VERSION 5.8 ;
BUSBITCHARS "[]" ;
DIVIDERCHAR "/" ;
UNITS
    DATABASE MICRONS 1000 ;
END UNITS

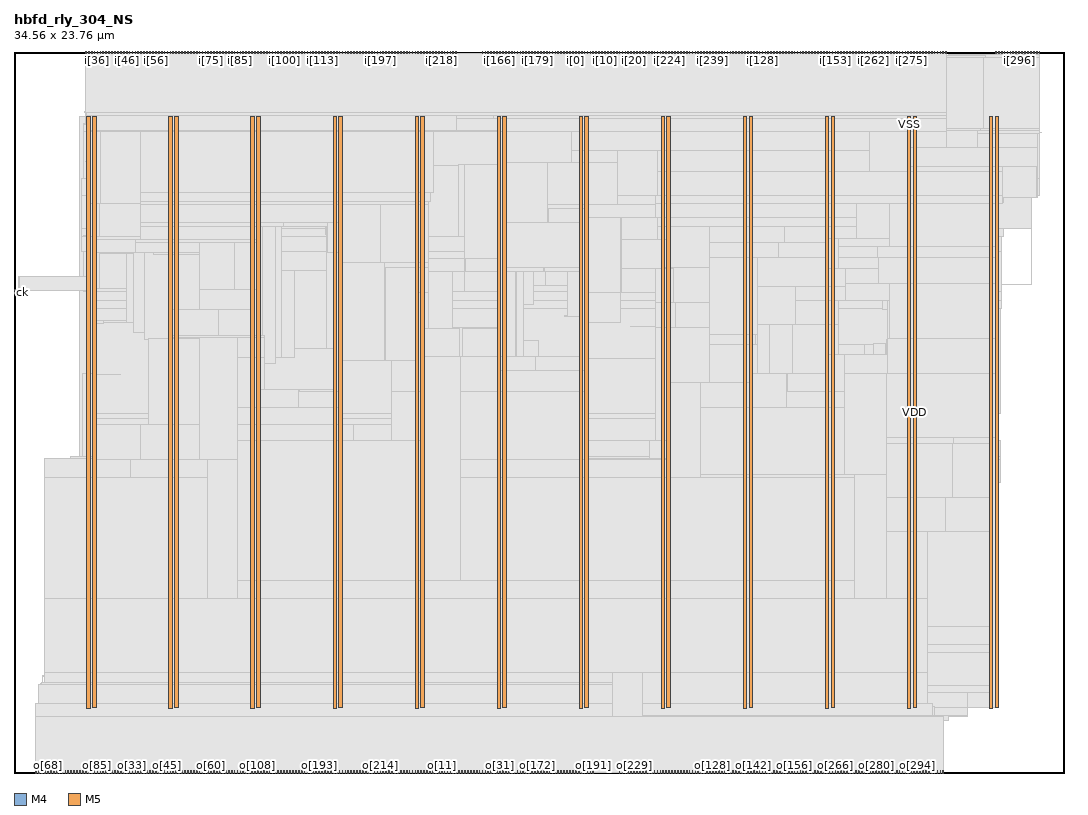
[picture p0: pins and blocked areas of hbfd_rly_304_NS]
MACRO hbfd_rly_304_NS
  FOREIGN hbfd_rly_304_NS 0 0 ;
  CLASS BLOCK ;
  SIZE 34.56 BY 23.76 ;
  PIN ck
    DIRECTION INPUT ;
    USE SIGNAL ;
    PORT
      LAYER M4 ;
        RECT  0 15.792 0.084 15.816 ;
    END
  END ck
  PIN i[0]
    DIRECTION INPUT ;
    USE SIGNAL ;
    PORT
      LAYER M5 ;
        RECT  18.48 23.676 18.504 23.76 ;
    END
  END i[0]
  PIN i[100]
    DIRECTION INPUT ;
    USE SIGNAL ;
    PORT
      LAYER M5 ;
        RECT  8.88 23.676 8.904 23.76 ;
    END
  END i[100]
  PIN i[101]
    DIRECTION INPUT ;
    USE SIGNAL ;
    PORT
      LAYER M5 ;
        RECT  8.976 23.676 9 23.76 ;
    END
  END i[101]
  PIN i[102]
    DIRECTION INPUT ;
    USE SIGNAL ;
    PORT
      LAYER M5 ;
        RECT  9.072 23.676 9.096 23.76 ;
    END
  END i[102]
  PIN i[103]
    DIRECTION INPUT ;
    USE SIGNAL ;
    PORT
      LAYER M5 ;
        RECT  9.168 23.676 9.192 23.76 ;
    END
  END i[103]
  PIN i[104]
    DIRECTION INPUT ;
    USE SIGNAL ;
    PORT
      LAYER M5 ;
        RECT  9.264 23.676 9.288 23.76 ;
    END
  END i[104]
  PIN i[105]
    DIRECTION INPUT ;
    USE SIGNAL ;
    PORT
      LAYER M5 ;
        RECT  9.36 23.676 9.384 23.76 ;
    END
  END i[105]
  PIN i[106]
    DIRECTION INPUT ;
    USE SIGNAL ;
    PORT
      LAYER M5 ;
        RECT  9.456 23.676 9.48 23.76 ;
    END
  END i[106]
  PIN i[107]
    DIRECTION INPUT ;
    USE SIGNAL ;
    PORT
      LAYER M5 ;
        RECT  9.552 23.676 9.576 23.76 ;
    END
  END i[107]
  PIN i[108]
    DIRECTION INPUT ;
    USE SIGNAL ;
    PORT
      LAYER M5 ;
        RECT  9.648 23.676 9.672 23.76 ;
    END
  END i[108]
  PIN i[109]
    DIRECTION INPUT ;
    USE SIGNAL ;
    PORT
      LAYER M5 ;
        RECT  9.744 23.676 9.768 23.76 ;
    END
  END i[109]
  PIN i[10]
    DIRECTION INPUT ;
    USE SIGNAL ;
    PORT
      LAYER M5 ;
        RECT  19.44 23.676 19.464 23.76 ;
    END
  END i[10]
  PIN i[110]
    DIRECTION INPUT ;
    USE SIGNAL ;
    PORT
      LAYER M5 ;
        RECT  9.84 23.676 9.864 23.76 ;
    END
  END i[110]
  PIN i[111]
    DIRECTION INPUT ;
    USE SIGNAL ;
    PORT
      LAYER M5 ;
        RECT  9.936 23.676 9.96 23.76 ;
    END
  END i[111]
  PIN i[112]
    DIRECTION INPUT ;
    USE SIGNAL ;
    PORT
      LAYER M5 ;
        RECT  10.032 23.676 10.056 23.76 ;
    END
  END i[112]
  PIN i[113]
    DIRECTION INPUT ;
    USE SIGNAL ;
    PORT
      LAYER M5 ;
        RECT  10.128 23.676 10.152 23.76 ;
    END
  END i[113]
  PIN i[114]
    DIRECTION INPUT ;
    USE SIGNAL ;
    PORT
      LAYER M5 ;
        RECT  10.224 23.676 10.248 23.76 ;
    END
  END i[114]
  PIN i[115]
    DIRECTION INPUT ;
    USE SIGNAL ;
    PORT
      LAYER M5 ;
        RECT  10.32 23.676 10.344 23.76 ;
    END
  END i[115]
  PIN i[116]
    DIRECTION INPUT ;
    USE SIGNAL ;
    PORT
      LAYER M5 ;
        RECT  10.416 23.676 10.44 23.76 ;
    END
  END i[116]
  PIN i[117]
    DIRECTION INPUT ;
    USE SIGNAL ;
    PORT
      LAYER M5 ;
        RECT  10.512 23.676 10.536 23.76 ;
    END
  END i[117]
  PIN i[118]
    DIRECTION INPUT ;
    USE SIGNAL ;
    PORT
      LAYER M5 ;
        RECT  10.608 23.676 10.632 23.76 ;
    END
  END i[118]
  PIN i[119]
    DIRECTION INPUT ;
    USE SIGNAL ;
    PORT
      LAYER M5 ;
        RECT  10.704 23.676 10.728 23.76 ;
    END
  END i[119]
  PIN i[11]
    DIRECTION INPUT ;
    USE SIGNAL ;
    PORT
      LAYER M5 ;
        RECT  19.536 23.676 19.56 23.76 ;
    END
  END i[11]
  PIN i[120]
    DIRECTION INPUT ;
    USE SIGNAL ;
    PORT
      LAYER M5 ;
        RECT  10.8 23.676 10.824 23.76 ;
    END
  END i[120]
  PIN i[121]
    DIRECTION INPUT ;
    USE SIGNAL ;
    PORT
      LAYER M5 ;
        RECT  10.896 23.676 10.92 23.76 ;
    END
  END i[121]
  PIN i[122]
    DIRECTION INPUT ;
    USE SIGNAL ;
    PORT
      LAYER M5 ;
        RECT  10.992 23.676 11.016 23.76 ;
    END
  END i[122]
  PIN i[123]
    DIRECTION INPUT ;
    USE SIGNAL ;
    PORT
      LAYER M5 ;
        RECT  11.088 23.676 11.112 23.76 ;
    END
  END i[123]
  PIN i[124]
    DIRECTION INPUT ;
    USE SIGNAL ;
    PORT
      LAYER M5 ;
        RECT  11.184 23.676 11.208 23.76 ;
    END
  END i[124]
  PIN i[125]
    DIRECTION INPUT ;
    USE SIGNAL ;
    PORT
      LAYER M5 ;
        RECT  11.28 23.676 11.304 23.76 ;
    END
  END i[125]
  PIN i[126]
    DIRECTION INPUT ;
    USE SIGNAL ;
    PORT
      LAYER M5 ;
        RECT  11.376 23.676 11.4 23.76 ;
    END
  END i[126]
  PIN i[127]
    DIRECTION INPUT ;
    USE SIGNAL ;
    PORT
      LAYER M5 ;
        RECT  11.472 23.676 11.496 23.76 ;
    END
  END i[127]
  PIN i[128]
    DIRECTION INPUT ;
    USE SIGNAL ;
    PORT
      LAYER M5 ;
        RECT  24.624 23.676 24.648 23.76 ;
    END
  END i[128]
  PIN i[129]
    DIRECTION INPUT ;
    USE SIGNAL ;
    PORT
      LAYER M5 ;
        RECT  24.72 23.676 24.744 23.76 ;
    END
  END i[129]
  PIN i[12]
    DIRECTION INPUT ;
    USE SIGNAL ;
    PORT
      LAYER M5 ;
        RECT  19.632 23.676 19.656 23.76 ;
    END
  END i[12]
  PIN i[130]
    DIRECTION INPUT ;
    USE SIGNAL ;
    PORT
      LAYER M5 ;
        RECT  24.816 23.676 24.84 23.76 ;
    END
  END i[130]
  PIN i[131]
    DIRECTION INPUT ;
    USE SIGNAL ;
    PORT
      LAYER M5 ;
        RECT  24.912 23.676 24.936 23.76 ;
    END
  END i[131]
  PIN i[132]
    DIRECTION INPUT ;
    USE SIGNAL ;
    PORT
      LAYER M5 ;
        RECT  25.008 23.676 25.032 23.76 ;
    END
  END i[132]
  PIN i[133]
    DIRECTION INPUT ;
    USE SIGNAL ;
    PORT
      LAYER M5 ;
        RECT  25.104 23.676 25.128 23.76 ;
    END
  END i[133]
  PIN i[134]
    DIRECTION INPUT ;
    USE SIGNAL ;
    PORT
      LAYER M5 ;
        RECT  25.2 23.676 25.224 23.76 ;
    END
  END i[134]
  PIN i[135]
    DIRECTION INPUT ;
    USE SIGNAL ;
    PORT
      LAYER M5 ;
        RECT  25.296 23.676 25.32 23.76 ;
    END
  END i[135]
  PIN i[136]
    DIRECTION INPUT ;
    USE SIGNAL ;
    PORT
      LAYER M5 ;
        RECT  25.392 23.676 25.416 23.76 ;
    END
  END i[136]
  PIN i[137]
    DIRECTION INPUT ;
    USE SIGNAL ;
    PORT
      LAYER M5 ;
        RECT  25.488 23.676 25.512 23.76 ;
    END
  END i[137]
  PIN i[138]
    DIRECTION INPUT ;
    USE SIGNAL ;
    PORT
      LAYER M5 ;
        RECT  25.584 23.676 25.608 23.76 ;
    END
  END i[138]
  PIN i[139]
    DIRECTION INPUT ;
    USE SIGNAL ;
    PORT
      LAYER M5 ;
        RECT  25.68 23.676 25.704 23.76 ;
    END
  END i[139]
  PIN i[13]
    DIRECTION INPUT ;
    USE SIGNAL ;
    PORT
      LAYER M5 ;
        RECT  19.728 23.676 19.752 23.76 ;
    END
  END i[13]
  PIN i[140]
    DIRECTION INPUT ;
    USE SIGNAL ;
    PORT
      LAYER M5 ;
        RECT  25.776 23.676 25.8 23.76 ;
    END
  END i[140]
  PIN i[141]
    DIRECTION INPUT ;
    USE SIGNAL ;
    PORT
      LAYER M5 ;
        RECT  25.872 23.676 25.896 23.76 ;
    END
  END i[141]
  PIN i[142]
    DIRECTION INPUT ;
    USE SIGNAL ;
    PORT
      LAYER M5 ;
        RECT  25.968 23.676 25.992 23.76 ;
    END
  END i[142]
  PIN i[143]
    DIRECTION INPUT ;
    USE SIGNAL ;
    PORT
      LAYER M5 ;
        RECT  26.064 23.676 26.088 23.76 ;
    END
  END i[143]
  PIN i[144]
    DIRECTION INPUT ;
    USE SIGNAL ;
    PORT
      LAYER M5 ;
        RECT  26.16 23.676 26.184 23.76 ;
    END
  END i[144]
  PIN i[145]
    DIRECTION INPUT ;
    USE SIGNAL ;
    PORT
      LAYER M5 ;
        RECT  26.256 23.676 26.28 23.76 ;
    END
  END i[145]
  PIN i[146]
    DIRECTION INPUT ;
    USE SIGNAL ;
    PORT
      LAYER M5 ;
        RECT  26.352 23.676 26.376 23.76 ;
    END
  END i[146]
  PIN i[147]
    DIRECTION INPUT ;
    USE SIGNAL ;
    PORT
      LAYER M5 ;
        RECT  26.448 23.676 26.472 23.76 ;
    END
  END i[147]
  PIN i[148]
    DIRECTION INPUT ;
    USE SIGNAL ;
    PORT
      LAYER M5 ;
        RECT  26.544 23.676 26.568 23.76 ;
    END
  END i[148]
  PIN i[149]
    DIRECTION INPUT ;
    USE SIGNAL ;
    PORT
      LAYER M5 ;
        RECT  26.64 23.676 26.664 23.76 ;
    END
  END i[149]
  PIN i[14]
    DIRECTION INPUT ;
    USE SIGNAL ;
    PORT
      LAYER M5 ;
        RECT  19.824 23.676 19.848 23.76 ;
    END
  END i[14]
  PIN i[150]
    DIRECTION INPUT ;
    USE SIGNAL ;
    PORT
      LAYER M5 ;
        RECT  26.736 23.676 26.76 23.76 ;
    END
  END i[150]
  PIN i[151]
    DIRECTION INPUT ;
    USE SIGNAL ;
    PORT
      LAYER M5 ;
        RECT  26.832 23.676 26.856 23.76 ;
    END
  END i[151]
  PIN i[152]
    DIRECTION INPUT ;
    USE SIGNAL ;
    PORT
      LAYER M5 ;
        RECT  26.928 23.676 26.952 23.76 ;
    END
  END i[152]
  PIN i[153]
    DIRECTION INPUT ;
    USE SIGNAL ;
    PORT
      LAYER M5 ;
        RECT  27.024 23.676 27.048 23.76 ;
    END
  END i[153]
  PIN i[154]
    DIRECTION INPUT ;
    USE SIGNAL ;
    PORT
      LAYER M5 ;
        RECT  27.12 23.676 27.144 23.76 ;
    END
  END i[154]
  PIN i[155]
    DIRECTION INPUT ;
    USE SIGNAL ;
    PORT
      LAYER M5 ;
        RECT  27.216 23.676 27.24 23.76 ;
    END
  END i[155]
  PIN i[156]
    DIRECTION INPUT ;
    USE SIGNAL ;
    PORT
      LAYER M5 ;
        RECT  27.312 23.676 27.336 23.76 ;
    END
  END i[156]
  PIN i[157]
    DIRECTION INPUT ;
    USE SIGNAL ;
    PORT
      LAYER M5 ;
        RECT  27.408 23.676 27.432 23.76 ;
    END
  END i[157]
  PIN i[158]
    DIRECTION INPUT ;
    USE SIGNAL ;
    PORT
      LAYER M5 ;
        RECT  27.504 23.676 27.528 23.76 ;
    END
  END i[158]
  PIN i[159]
    DIRECTION INPUT ;
    USE SIGNAL ;
    PORT
      LAYER M5 ;
        RECT  27.6 23.676 27.624 23.76 ;
    END
  END i[159]
  PIN i[15]
    DIRECTION INPUT ;
    USE SIGNAL ;
    PORT
      LAYER M5 ;
        RECT  19.92 23.676 19.944 23.76 ;
    END
  END i[15]
  PIN i[160]
    DIRECTION INPUT ;
    USE SIGNAL ;
    PORT
      LAYER M5 ;
        RECT  15.408 23.676 15.432 23.76 ;
    END
  END i[160]
  PIN i[161]
    DIRECTION INPUT ;
    USE SIGNAL ;
    PORT
      LAYER M5 ;
        RECT  15.504 23.676 15.528 23.76 ;
    END
  END i[161]
  PIN i[162]
    DIRECTION INPUT ;
    USE SIGNAL ;
    PORT
      LAYER M5 ;
        RECT  15.6 23.676 15.624 23.76 ;
    END
  END i[162]
  PIN i[163]
    DIRECTION INPUT ;
    USE SIGNAL ;
    PORT
      LAYER M5 ;
        RECT  15.696 23.676 15.72 23.76 ;
    END
  END i[163]
  PIN i[164]
    DIRECTION INPUT ;
    USE SIGNAL ;
    PORT
      LAYER M5 ;
        RECT  15.792 23.676 15.816 23.76 ;
    END
  END i[164]
  PIN i[165]
    DIRECTION INPUT ;
    USE SIGNAL ;
    PORT
      LAYER M5 ;
        RECT  15.888 23.676 15.912 23.76 ;
    END
  END i[165]
  PIN i[166]
    DIRECTION INPUT ;
    USE SIGNAL ;
    PORT
      LAYER M5 ;
        RECT  15.984 23.676 16.008 23.76 ;
    END
  END i[166]
  PIN i[167]
    DIRECTION INPUT ;
    USE SIGNAL ;
    PORT
      LAYER M5 ;
        RECT  16.08 23.676 16.104 23.76 ;
    END
  END i[167]
  PIN i[168]
    DIRECTION INPUT ;
    USE SIGNAL ;
    PORT
      LAYER M5 ;
        RECT  16.176 23.676 16.2 23.76 ;
    END
  END i[168]
  PIN i[169]
    DIRECTION INPUT ;
    USE SIGNAL ;
    PORT
      LAYER M5 ;
        RECT  16.272 23.676 16.296 23.76 ;
    END
  END i[169]
  PIN i[16]
    DIRECTION INPUT ;
    USE SIGNAL ;
    PORT
      LAYER M5 ;
        RECT  20.016 23.676 20.04 23.76 ;
    END
  END i[16]
  PIN i[170]
    DIRECTION INPUT ;
    USE SIGNAL ;
    PORT
      LAYER M5 ;
        RECT  16.368 23.676 16.392 23.76 ;
    END
  END i[170]
  PIN i[171]
    DIRECTION INPUT ;
    USE SIGNAL ;
    PORT
      LAYER M5 ;
        RECT  16.464 23.676 16.488 23.76 ;
    END
  END i[171]
  PIN i[172]
    DIRECTION INPUT ;
    USE SIGNAL ;
    PORT
      LAYER M5 ;
        RECT  16.56 23.676 16.584 23.76 ;
    END
  END i[172]
  PIN i[173]
    DIRECTION INPUT ;
    USE SIGNAL ;
    PORT
      LAYER M5 ;
        RECT  16.656 23.676 16.68 23.76 ;
    END
  END i[173]
  PIN i[174]
    DIRECTION INPUT ;
    USE SIGNAL ;
    PORT
      LAYER M5 ;
        RECT  16.752 23.676 16.776 23.76 ;
    END
  END i[174]
  PIN i[175]
    DIRECTION INPUT ;
    USE SIGNAL ;
    PORT
      LAYER M5 ;
        RECT  16.848 23.676 16.872 23.76 ;
    END
  END i[175]
  PIN i[176]
    DIRECTION INPUT ;
    USE SIGNAL ;
    PORT
      LAYER M5 ;
        RECT  16.944 23.676 16.968 23.76 ;
    END
  END i[176]
  PIN i[177]
    DIRECTION INPUT ;
    USE SIGNAL ;
    PORT
      LAYER M5 ;
        RECT  17.04 23.676 17.064 23.76 ;
    END
  END i[177]
  PIN i[178]
    DIRECTION INPUT ;
    USE SIGNAL ;
    PORT
      LAYER M5 ;
        RECT  17.136 23.676 17.16 23.76 ;
    END
  END i[178]
  PIN i[179]
    DIRECTION INPUT ;
    USE SIGNAL ;
    PORT
      LAYER M5 ;
        RECT  17.232 23.676 17.256 23.76 ;
    END
  END i[179]
  PIN i[17]
    DIRECTION INPUT ;
    USE SIGNAL ;
    PORT
      LAYER M5 ;
        RECT  20.112 23.676 20.136 23.76 ;
    END
  END i[17]
  PIN i[180]
    DIRECTION INPUT ;
    USE SIGNAL ;
    PORT
      LAYER M5 ;
        RECT  17.328 23.676 17.352 23.76 ;
    END
  END i[180]
  PIN i[181]
    DIRECTION INPUT ;
    USE SIGNAL ;
    PORT
      LAYER M5 ;
        RECT  17.424 23.676 17.448 23.76 ;
    END
  END i[181]
  PIN i[182]
    DIRECTION INPUT ;
    USE SIGNAL ;
    PORT
      LAYER M5 ;
        RECT  17.52 23.676 17.544 23.76 ;
    END
  END i[182]
  PIN i[183]
    DIRECTION INPUT ;
    USE SIGNAL ;
    PORT
      LAYER M5 ;
        RECT  17.616 23.676 17.64 23.76 ;
    END
  END i[183]
  PIN i[184]
    DIRECTION INPUT ;
    USE SIGNAL ;
    PORT
      LAYER M5 ;
        RECT  17.712 23.676 17.736 23.76 ;
    END
  END i[184]
  PIN i[185]
    DIRECTION INPUT ;
    USE SIGNAL ;
    PORT
      LAYER M5 ;
        RECT  17.808 23.676 17.832 23.76 ;
    END
  END i[185]
  PIN i[186]
    DIRECTION INPUT ;
    USE SIGNAL ;
    PORT
      LAYER M5 ;
        RECT  17.904 23.676 17.928 23.76 ;
    END
  END i[186]
  PIN i[187]
    DIRECTION INPUT ;
    USE SIGNAL ;
    PORT
      LAYER M5 ;
        RECT  18 23.676 18.024 23.76 ;
    END
  END i[187]
  PIN i[188]
    DIRECTION INPUT ;
    USE SIGNAL ;
    PORT
      LAYER M5 ;
        RECT  18.096 23.676 18.12 23.76 ;
    END
  END i[188]
  PIN i[189]
    DIRECTION INPUT ;
    USE SIGNAL ;
    PORT
      LAYER M5 ;
        RECT  18.192 23.676 18.216 23.76 ;
    END
  END i[189]
  PIN i[18]
    DIRECTION INPUT ;
    USE SIGNAL ;
    PORT
      LAYER M5 ;
        RECT  20.208 23.676 20.232 23.76 ;
    END
  END i[18]
  PIN i[190]
    DIRECTION INPUT ;
    USE SIGNAL ;
    PORT
      LAYER M5 ;
        RECT  18.288 23.676 18.312 23.76 ;
    END
  END i[190]
  PIN i[191]
    DIRECTION INPUT ;
    USE SIGNAL ;
    PORT
      LAYER M5 ;
        RECT  18.384 23.676 18.408 23.76 ;
    END
  END i[191]
  PIN i[192]
    DIRECTION INPUT ;
    USE SIGNAL ;
    PORT
      LAYER M5 ;
        RECT  11.568 23.676 11.592 23.76 ;
    END
  END i[192]
  PIN i[193]
    DIRECTION INPUT ;
    USE SIGNAL ;
    PORT
      LAYER M5 ;
        RECT  11.664 23.676 11.688 23.76 ;
    END
  END i[193]
  PIN i[194]
    DIRECTION INPUT ;
    USE SIGNAL ;
    PORT
      LAYER M5 ;
        RECT  11.76 23.676 11.784 23.76 ;
    END
  END i[194]
  PIN i[195]
    DIRECTION INPUT ;
    USE SIGNAL ;
    PORT
      LAYER M5 ;
        RECT  11.856 23.676 11.88 23.76 ;
    END
  END i[195]
  PIN i[196]
    DIRECTION INPUT ;
    USE SIGNAL ;
    PORT
      LAYER M5 ;
        RECT  11.952 23.676 11.976 23.76 ;
    END
  END i[196]
  PIN i[197]
    DIRECTION INPUT ;
    USE SIGNAL ;
    PORT
      LAYER M5 ;
        RECT  12.048 23.676 12.072 23.76 ;
    END
  END i[197]
  PIN i[198]
    DIRECTION INPUT ;
    USE SIGNAL ;
    PORT
      LAYER M5 ;
        RECT  12.144 23.676 12.168 23.76 ;
    END
  END i[198]
  PIN i[199]
    DIRECTION INPUT ;
    USE SIGNAL ;
    PORT
      LAYER M5 ;
        RECT  12.24 23.676 12.264 23.76 ;
    END
  END i[199]
  PIN i[19]
    DIRECTION INPUT ;
    USE SIGNAL ;
    PORT
      LAYER M5 ;
        RECT  20.304 23.676 20.328 23.76 ;
    END
  END i[19]
  PIN i[1]
    DIRECTION INPUT ;
    USE SIGNAL ;
    PORT
      LAYER M5 ;
        RECT  18.576 23.676 18.6 23.76 ;
    END
  END i[1]
  PIN i[200]
    DIRECTION INPUT ;
    USE SIGNAL ;
    PORT
      LAYER M5 ;
        RECT  12.336 23.676 12.36 23.76 ;
    END
  END i[200]
  PIN i[201]
    DIRECTION INPUT ;
    USE SIGNAL ;
    PORT
      LAYER M5 ;
        RECT  12.432 23.676 12.456 23.76 ;
    END
  END i[201]
  PIN i[202]
    DIRECTION INPUT ;
    USE SIGNAL ;
    PORT
      LAYER M5 ;
        RECT  12.528 23.676 12.552 23.76 ;
    END
  END i[202]
  PIN i[203]
    DIRECTION INPUT ;
    USE SIGNAL ;
    PORT
      LAYER M5 ;
        RECT  12.624 23.676 12.648 23.76 ;
    END
  END i[203]
  PIN i[204]
    DIRECTION INPUT ;
    USE SIGNAL ;
    PORT
      LAYER M5 ;
        RECT  12.72 23.676 12.744 23.76 ;
    END
  END i[204]
  PIN i[205]
    DIRECTION INPUT ;
    USE SIGNAL ;
    PORT
      LAYER M5 ;
        RECT  12.816 23.676 12.84 23.76 ;
    END
  END i[205]
  PIN i[206]
    DIRECTION INPUT ;
    USE SIGNAL ;
    PORT
      LAYER M5 ;
        RECT  12.912 23.676 12.936 23.76 ;
    END
  END i[206]
  PIN i[207]
    DIRECTION INPUT ;
    USE SIGNAL ;
    PORT
      LAYER M5 ;
        RECT  13.008 23.676 13.032 23.76 ;
    END
  END i[207]
  PIN i[208]
    DIRECTION INPUT ;
    USE SIGNAL ;
    PORT
      LAYER M5 ;
        RECT  13.104 23.676 13.128 23.76 ;
    END
  END i[208]
  PIN i[209]
    DIRECTION INPUT ;
    USE SIGNAL ;
    PORT
      LAYER M5 ;
        RECT  13.2 23.676 13.224 23.76 ;
    END
  END i[209]
  PIN i[20]
    DIRECTION INPUT ;
    USE SIGNAL ;
    PORT
      LAYER M5 ;
        RECT  20.4 23.676 20.424 23.76 ;
    END
  END i[20]
  PIN i[210]
    DIRECTION INPUT ;
    USE SIGNAL ;
    PORT
      LAYER M5 ;
        RECT  13.296 23.676 13.32 23.76 ;
    END
  END i[210]
  PIN i[211]
    DIRECTION INPUT ;
    USE SIGNAL ;
    PORT
      LAYER M5 ;
        RECT  13.392 23.676 13.416 23.76 ;
    END
  END i[211]
  PIN i[212]
    DIRECTION INPUT ;
    USE SIGNAL ;
    PORT
      LAYER M5 ;
        RECT  13.488 23.676 13.512 23.76 ;
    END
  END i[212]
  PIN i[213]
    DIRECTION INPUT ;
    USE SIGNAL ;
    PORT
      LAYER M5 ;
        RECT  13.584 23.676 13.608 23.76 ;
    END
  END i[213]
  PIN i[214]
    DIRECTION INPUT ;
    USE SIGNAL ;
    PORT
      LAYER M5 ;
        RECT  13.68 23.676 13.704 23.76 ;
    END
  END i[214]
  PIN i[215]
    DIRECTION INPUT ;
    USE SIGNAL ;
    PORT
      LAYER M5 ;
        RECT  13.776 23.676 13.8 23.76 ;
    END
  END i[215]
  PIN i[216]
    DIRECTION INPUT ;
    USE SIGNAL ;
    PORT
      LAYER M5 ;
        RECT  13.872 23.676 13.896 23.76 ;
    END
  END i[216]
  PIN i[217]
    DIRECTION INPUT ;
    USE SIGNAL ;
    PORT
      LAYER M5 ;
        RECT  13.968 23.676 13.992 23.76 ;
    END
  END i[217]
  PIN i[218]
    DIRECTION INPUT ;
    USE SIGNAL ;
    PORT
      LAYER M5 ;
        RECT  14.064 23.676 14.088 23.76 ;
    END
  END i[218]
  PIN i[219]
    DIRECTION INPUT ;
    USE SIGNAL ;
    PORT
      LAYER M5 ;
        RECT  14.16 23.676 14.184 23.76 ;
    END
  END i[219]
  PIN i[21]
    DIRECTION INPUT ;
    USE SIGNAL ;
    PORT
      LAYER M5 ;
        RECT  20.496 23.676 20.52 23.76 ;
    END
  END i[21]
  PIN i[220]
    DIRECTION INPUT ;
    USE SIGNAL ;
    PORT
      LAYER M5 ;
        RECT  14.256 23.676 14.28 23.76 ;
    END
  END i[220]
  PIN i[221]
    DIRECTION INPUT ;
    USE SIGNAL ;
    PORT
      LAYER M5 ;
        RECT  14.352 23.676 14.376 23.76 ;
    END
  END i[221]
  PIN i[222]
    DIRECTION INPUT ;
    USE SIGNAL ;
    PORT
      LAYER M5 ;
        RECT  14.448 23.676 14.472 23.76 ;
    END
  END i[222]
  PIN i[223]
    DIRECTION INPUT ;
    USE SIGNAL ;
    PORT
      LAYER M5 ;
        RECT  14.544 23.676 14.568 23.76 ;
    END
  END i[223]
  PIN i[224]
    DIRECTION INPUT ;
    USE SIGNAL ;
    PORT
      LAYER M5 ;
        RECT  21.552 23.676 21.576 23.76 ;
    END
  END i[224]
  PIN i[225]
    DIRECTION INPUT ;
    USE SIGNAL ;
    PORT
      LAYER M5 ;
        RECT  21.648 23.676 21.672 23.76 ;
    END
  END i[225]
  PIN i[226]
    DIRECTION INPUT ;
    USE SIGNAL ;
    PORT
      LAYER M5 ;
        RECT  21.744 23.676 21.768 23.76 ;
    END
  END i[226]
  PIN i[227]
    DIRECTION INPUT ;
    USE SIGNAL ;
    PORT
      LAYER M5 ;
        RECT  21.84 23.676 21.864 23.76 ;
    END
  END i[227]
  PIN i[228]
    DIRECTION INPUT ;
    USE SIGNAL ;
    PORT
      LAYER M5 ;
        RECT  21.936 23.676 21.96 23.76 ;
    END
  END i[228]
  PIN i[229]
    DIRECTION INPUT ;
    USE SIGNAL ;
    PORT
      LAYER M5 ;
        RECT  22.032 23.676 22.056 23.76 ;
    END
  END i[229]
  PIN i[22]
    DIRECTION INPUT ;
    USE SIGNAL ;
    PORT
      LAYER M5 ;
        RECT  20.592 23.676 20.616 23.76 ;
    END
  END i[22]
  PIN i[230]
    DIRECTION INPUT ;
    USE SIGNAL ;
    PORT
      LAYER M5 ;
        RECT  22.128 23.676 22.152 23.76 ;
    END
  END i[230]
  PIN i[231]
    DIRECTION INPUT ;
    USE SIGNAL ;
    PORT
      LAYER M5 ;
        RECT  22.224 23.676 22.248 23.76 ;
    END
  END i[231]
  PIN i[232]
    DIRECTION INPUT ;
    USE SIGNAL ;
    PORT
      LAYER M5 ;
        RECT  22.32 23.676 22.344 23.76 ;
    END
  END i[232]
  PIN i[233]
    DIRECTION INPUT ;
    USE SIGNAL ;
    PORT
      LAYER M5 ;
        RECT  22.416 23.676 22.44 23.76 ;
    END
  END i[233]
  PIN i[234]
    DIRECTION INPUT ;
    USE SIGNAL ;
    PORT
      LAYER M5 ;
        RECT  22.512 23.676 22.536 23.76 ;
    END
  END i[234]
  PIN i[235]
    DIRECTION INPUT ;
    USE SIGNAL ;
    PORT
      LAYER M5 ;
        RECT  22.608 23.676 22.632 23.76 ;
    END
  END i[235]
  PIN i[236]
    DIRECTION INPUT ;
    USE SIGNAL ;
    PORT
      LAYER M5 ;
        RECT  22.704 23.676 22.728 23.76 ;
    END
  END i[236]
  PIN i[237]
    DIRECTION INPUT ;
    USE SIGNAL ;
    PORT
      LAYER M5 ;
        RECT  22.8 23.676 22.824 23.76 ;
    END
  END i[237]
  PIN i[238]
    DIRECTION INPUT ;
    USE SIGNAL ;
    PORT
      LAYER M5 ;
        RECT  22.896 23.676 22.92 23.76 ;
    END
  END i[238]
  PIN i[239]
    DIRECTION INPUT ;
    USE SIGNAL ;
    PORT
      LAYER M5 ;
        RECT  22.992 23.676 23.016 23.76 ;
    END
  END i[239]
  PIN i[23]
    DIRECTION INPUT ;
    USE SIGNAL ;
    PORT
      LAYER M5 ;
        RECT  20.688 23.676 20.712 23.76 ;
    END
  END i[23]
  PIN i[240]
    DIRECTION INPUT ;
    USE SIGNAL ;
    PORT
      LAYER M5 ;
        RECT  23.088 23.676 23.112 23.76 ;
    END
  END i[240]
  PIN i[241]
    DIRECTION INPUT ;
    USE SIGNAL ;
    PORT
      LAYER M5 ;
        RECT  23.184 23.676 23.208 23.76 ;
    END
  END i[241]
  PIN i[242]
    DIRECTION INPUT ;
    USE SIGNAL ;
    PORT
      LAYER M5 ;
        RECT  23.28 23.676 23.304 23.76 ;
    END
  END i[242]
  PIN i[243]
    DIRECTION INPUT ;
    USE SIGNAL ;
    PORT
      LAYER M5 ;
        RECT  23.376 23.676 23.4 23.76 ;
    END
  END i[243]
  PIN i[244]
    DIRECTION INPUT ;
    USE SIGNAL ;
    PORT
      LAYER M5 ;
        RECT  23.472 23.676 23.496 23.76 ;
    END
  END i[244]
  PIN i[245]
    DIRECTION INPUT ;
    USE SIGNAL ;
    PORT
      LAYER M5 ;
        RECT  23.568 23.676 23.592 23.76 ;
    END
  END i[245]
  PIN i[246]
    DIRECTION INPUT ;
    USE SIGNAL ;
    PORT
      LAYER M5 ;
        RECT  23.664 23.676 23.688 23.76 ;
    END
  END i[246]
  PIN i[247]
    DIRECTION INPUT ;
    USE SIGNAL ;
    PORT
      LAYER M5 ;
        RECT  23.76 23.676 23.784 23.76 ;
    END
  END i[247]
  PIN i[248]
    DIRECTION INPUT ;
    USE SIGNAL ;
    PORT
      LAYER M5 ;
        RECT  23.856 23.676 23.88 23.76 ;
    END
  END i[248]
  PIN i[249]
    DIRECTION INPUT ;
    USE SIGNAL ;
    PORT
      LAYER M5 ;
        RECT  23.952 23.676 23.976 23.76 ;
    END
  END i[249]
  PIN i[24]
    DIRECTION INPUT ;
    USE SIGNAL ;
    PORT
      LAYER M5 ;
        RECT  20.784 23.676 20.808 23.76 ;
    END
  END i[24]
  PIN i[250]
    DIRECTION INPUT ;
    USE SIGNAL ;
    PORT
      LAYER M5 ;
        RECT  24.048 23.676 24.072 23.76 ;
    END
  END i[250]
  PIN i[251]
    DIRECTION INPUT ;
    USE SIGNAL ;
    PORT
      LAYER M5 ;
        RECT  24.144 23.676 24.168 23.76 ;
    END
  END i[251]
  PIN i[252]
    DIRECTION INPUT ;
    USE SIGNAL ;
    PORT
      LAYER M5 ;
        RECT  24.24 23.676 24.264 23.76 ;
    END
  END i[252]
  PIN i[253]
    DIRECTION INPUT ;
    USE SIGNAL ;
    PORT
      LAYER M5 ;
        RECT  24.336 23.676 24.36 23.76 ;
    END
  END i[253]
  PIN i[254]
    DIRECTION INPUT ;
    USE SIGNAL ;
    PORT
      LAYER M5 ;
        RECT  24.432 23.676 24.456 23.76 ;
    END
  END i[254]
  PIN i[255]
    DIRECTION INPUT ;
    USE SIGNAL ;
    PORT
      LAYER M5 ;
        RECT  24.528 23.676 24.552 23.76 ;
    END
  END i[255]
  PIN i[256]
    DIRECTION INPUT ;
    USE SIGNAL ;
    PORT
      LAYER M5 ;
        RECT  27.696 23.676 27.72 23.76 ;
    END
  END i[256]
  PIN i[257]
    DIRECTION INPUT ;
    USE SIGNAL ;
    PORT
      LAYER M5 ;
        RECT  27.792 23.676 27.816 23.76 ;
    END
  END i[257]
  PIN i[258]
    DIRECTION INPUT ;
    USE SIGNAL ;
    PORT
      LAYER M5 ;
        RECT  27.888 23.676 27.912 23.76 ;
    END
  END i[258]
  PIN i[259]
    DIRECTION INPUT ;
    USE SIGNAL ;
    PORT
      LAYER M5 ;
        RECT  27.984 23.676 28.008 23.76 ;
    END
  END i[259]
  PIN i[25]
    DIRECTION INPUT ;
    USE SIGNAL ;
    PORT
      LAYER M5 ;
        RECT  20.88 23.676 20.904 23.76 ;
    END
  END i[25]
  PIN i[260]
    DIRECTION INPUT ;
    USE SIGNAL ;
    PORT
      LAYER M5 ;
        RECT  28.08 23.676 28.104 23.76 ;
    END
  END i[260]
  PIN i[261]
    DIRECTION INPUT ;
    USE SIGNAL ;
    PORT
      LAYER M5 ;
        RECT  28.176 23.676 28.2 23.76 ;
    END
  END i[261]
  PIN i[262]
    DIRECTION INPUT ;
    USE SIGNAL ;
    PORT
      LAYER M5 ;
        RECT  28.272 23.676 28.296 23.76 ;
    END
  END i[262]
  PIN i[263]
    DIRECTION INPUT ;
    USE SIGNAL ;
    PORT
      LAYER M5 ;
        RECT  28.368 23.676 28.392 23.76 ;
    END
  END i[263]
  PIN i[264]
    DIRECTION INPUT ;
    USE SIGNAL ;
    PORT
      LAYER M5 ;
        RECT  28.464 23.676 28.488 23.76 ;
    END
  END i[264]
  PIN i[265]
    DIRECTION INPUT ;
    USE SIGNAL ;
    PORT
      LAYER M5 ;
        RECT  28.56 23.676 28.584 23.76 ;
    END
  END i[265]
  PIN i[266]
    DIRECTION INPUT ;
    USE SIGNAL ;
    PORT
      LAYER M5 ;
        RECT  28.656 23.676 28.68 23.76 ;
    END
  END i[266]
  PIN i[267]
    DIRECTION INPUT ;
    USE SIGNAL ;
    PORT
      LAYER M5 ;
        RECT  28.752 23.676 28.776 23.76 ;
    END
  END i[267]
  PIN i[268]
    DIRECTION INPUT ;
    USE SIGNAL ;
    PORT
      LAYER M5 ;
        RECT  28.848 23.676 28.872 23.76 ;
    END
  END i[268]
  PIN i[269]
    DIRECTION INPUT ;
    USE SIGNAL ;
    PORT
      LAYER M5 ;
        RECT  28.944 23.676 28.968 23.76 ;
    END
  END i[269]
  PIN i[26]
    DIRECTION INPUT ;
    USE SIGNAL ;
    PORT
      LAYER M5 ;
        RECT  20.976 23.676 21 23.76 ;
    END
  END i[26]
  PIN i[270]
    DIRECTION INPUT ;
    USE SIGNAL ;
    PORT
      LAYER M5 ;
        RECT  29.04 23.676 29.064 23.76 ;
    END
  END i[270]
  PIN i[271]
    DIRECTION INPUT ;
    USE SIGNAL ;
    PORT
      LAYER M5 ;
        RECT  29.136 23.676 29.16 23.76 ;
    END
  END i[271]
  PIN i[272]
    DIRECTION INPUT ;
    USE SIGNAL ;
    PORT
      LAYER M5 ;
        RECT  29.232 23.676 29.256 23.76 ;
    END
  END i[272]
  PIN i[273]
    DIRECTION INPUT ;
    USE SIGNAL ;
    PORT
      LAYER M5 ;
        RECT  29.328 23.676 29.352 23.76 ;
    END
  END i[273]
  PIN i[274]
    DIRECTION INPUT ;
    USE SIGNAL ;
    PORT
      LAYER M5 ;
        RECT  29.424 23.676 29.448 23.76 ;
    END
  END i[274]
  PIN i[275]
    DIRECTION INPUT ;
    USE SIGNAL ;
    PORT
      LAYER M5 ;
        RECT  29.52 23.676 29.544 23.76 ;
    END
  END i[275]
  PIN i[276]
    DIRECTION INPUT ;
    USE SIGNAL ;
    PORT
      LAYER M5 ;
        RECT  29.616 23.676 29.64 23.76 ;
    END
  END i[276]
  PIN i[277]
    DIRECTION INPUT ;
    USE SIGNAL ;
    PORT
      LAYER M5 ;
        RECT  29.712 23.676 29.736 23.76 ;
    END
  END i[277]
  PIN i[278]
    DIRECTION INPUT ;
    USE SIGNAL ;
    PORT
      LAYER M5 ;
        RECT  29.808 23.676 29.832 23.76 ;
    END
  END i[278]
  PIN i[279]
    DIRECTION INPUT ;
    USE SIGNAL ;
    PORT
      LAYER M5 ;
        RECT  29.904 23.676 29.928 23.76 ;
    END
  END i[279]
  PIN i[27]
    DIRECTION INPUT ;
    USE SIGNAL ;
    PORT
      LAYER M5 ;
        RECT  21.072 23.676 21.096 23.76 ;
    END
  END i[27]
  PIN i[280]
    DIRECTION INPUT ;
    USE SIGNAL ;
    PORT
      LAYER M5 ;
        RECT  30 23.676 30.024 23.76 ;
    END
  END i[280]
  PIN i[281]
    DIRECTION INPUT ;
    USE SIGNAL ;
    PORT
      LAYER M5 ;
        RECT  30.096 23.676 30.12 23.76 ;
    END
  END i[281]
  PIN i[282]
    DIRECTION INPUT ;
    USE SIGNAL ;
    PORT
      LAYER M5 ;
        RECT  30.192 23.676 30.216 23.76 ;
    END
  END i[282]
  PIN i[283]
    DIRECTION INPUT ;
    USE SIGNAL ;
    PORT
      LAYER M5 ;
        RECT  30.288 23.676 30.312 23.76 ;
    END
  END i[283]
  PIN i[284]
    DIRECTION INPUT ;
    USE SIGNAL ;
    PORT
      LAYER M5 ;
        RECT  30.384 23.676 30.408 23.76 ;
    END
  END i[284]
  PIN i[285]
    DIRECTION INPUT ;
    USE SIGNAL ;
    PORT
      LAYER M5 ;
        RECT  30.48 23.676 30.504 23.76 ;
    END
  END i[285]
  PIN i[286]
    DIRECTION INPUT ;
    USE SIGNAL ;
    PORT
      LAYER M5 ;
        RECT  30.576 23.676 30.6 23.76 ;
    END
  END i[286]
  PIN i[287]
    DIRECTION INPUT ;
    USE SIGNAL ;
    PORT
      LAYER M5 ;
        RECT  30.672 23.676 30.696 23.76 ;
    END
  END i[287]
  PIN i[288]
    DIRECTION INPUT ;
    USE SIGNAL ;
    PORT
      LAYER M5 ;
        RECT  32.304 23.676 32.328 23.76 ;
    END
  END i[288]
  PIN i[289]
    DIRECTION INPUT ;
    USE SIGNAL ;
    PORT
      LAYER M5 ;
        RECT  32.4 23.676 32.424 23.76 ;
    END
  END i[289]
  PIN i[28]
    DIRECTION INPUT ;
    USE SIGNAL ;
    PORT
      LAYER M5 ;
        RECT  21.168 23.676 21.192 23.76 ;
    END
  END i[28]
  PIN i[290]
    DIRECTION INPUT ;
    USE SIGNAL ;
    PORT
      LAYER M5 ;
        RECT  32.496 23.676 32.52 23.76 ;
    END
  END i[290]
  PIN i[291]
    DIRECTION INPUT ;
    USE SIGNAL ;
    PORT
      LAYER M5 ;
        RECT  32.592 23.676 32.616 23.76 ;
    END
  END i[291]
  PIN i[292]
    DIRECTION INPUT ;
    USE SIGNAL ;
    PORT
      LAYER M5 ;
        RECT  32.688 23.676 32.712 23.76 ;
    END
  END i[292]
  PIN i[293]
    DIRECTION INPUT ;
    USE SIGNAL ;
    PORT
      LAYER M5 ;
        RECT  32.784 23.676 32.808 23.76 ;
    END
  END i[293]
  PIN i[294]
    DIRECTION INPUT ;
    USE SIGNAL ;
    PORT
      LAYER M5 ;
        RECT  32.88 23.676 32.904 23.76 ;
    END
  END i[294]
  PIN i[295]
    DIRECTION INPUT ;
    USE SIGNAL ;
    PORT
      LAYER M5 ;
        RECT  32.976 23.676 33 23.76 ;
    END
  END i[295]
  PIN i[296]
    DIRECTION INPUT ;
    USE SIGNAL ;
    PORT
      LAYER M5 ;
        RECT  33.072 23.676 33.096 23.76 ;
    END
  END i[296]
  PIN i[297]
    DIRECTION INPUT ;
    USE SIGNAL ;
    PORT
      LAYER M5 ;
        RECT  33.168 23.676 33.192 23.76 ;
    END
  END i[297]
  PIN i[298]
    DIRECTION INPUT ;
    USE SIGNAL ;
    PORT
      LAYER M5 ;
        RECT  33.264 23.676 33.288 23.76 ;
    END
  END i[298]
  PIN i[299]
    DIRECTION INPUT ;
    USE SIGNAL ;
    PORT
      LAYER M5 ;
        RECT  33.36 23.676 33.384 23.76 ;
    END
  END i[299]
  PIN i[29]
    DIRECTION INPUT ;
    USE SIGNAL ;
    PORT
      LAYER M5 ;
        RECT  21.264 23.676 21.288 23.76 ;
    END
  END i[29]
  PIN i[2]
    DIRECTION INPUT ;
    USE SIGNAL ;
    PORT
      LAYER M5 ;
        RECT  18.672 23.676 18.696 23.76 ;
    END
  END i[2]
  PIN i[300]
    DIRECTION INPUT ;
    USE SIGNAL ;
    PORT
      LAYER M5 ;
        RECT  33.456 23.676 33.48 23.76 ;
    END
  END i[300]
  PIN i[301]
    DIRECTION INPUT ;
    USE SIGNAL ;
    PORT
      LAYER M5 ;
        RECT  33.552 23.676 33.576 23.76 ;
    END
  END i[301]
  PIN i[302]
    DIRECTION INPUT ;
    USE SIGNAL ;
    PORT
      LAYER M5 ;
        RECT  33.648 23.676 33.672 23.76 ;
    END
  END i[302]
  PIN i[303]
    DIRECTION INPUT ;
    USE SIGNAL ;
    PORT
      LAYER M5 ;
        RECT  33.744 23.676 33.768 23.76 ;
    END
  END i[303]
  PIN i[30]
    DIRECTION INPUT ;
    USE SIGNAL ;
    PORT
      LAYER M5 ;
        RECT  21.36 23.676 21.384 23.76 ;
    END
  END i[30]
  PIN i[31]
    DIRECTION INPUT ;
    USE SIGNAL ;
    PORT
      LAYER M5 ;
        RECT  21.456 23.676 21.48 23.76 ;
    END
  END i[31]
  PIN i[32]
    DIRECTION INPUT ;
    USE SIGNAL ;
    PORT
      LAYER M5 ;
        RECT  2.352 23.676 2.376 23.76 ;
    END
  END i[32]
  PIN i[33]
    DIRECTION INPUT ;
    USE SIGNAL ;
    PORT
      LAYER M5 ;
        RECT  2.448 23.676 2.472 23.76 ;
    END
  END i[33]
  PIN i[34]
    DIRECTION INPUT ;
    USE SIGNAL ;
    PORT
      LAYER M5 ;
        RECT  2.544 23.676 2.568 23.76 ;
    END
  END i[34]
  PIN i[35]
    DIRECTION INPUT ;
    USE SIGNAL ;
    PORT
      LAYER M5 ;
        RECT  2.64 23.676 2.664 23.76 ;
    END
  END i[35]
  PIN i[36]
    DIRECTION INPUT ;
    USE SIGNAL ;
    PORT
      LAYER M5 ;
        RECT  2.736 23.676 2.76 23.76 ;
    END
  END i[36]
  PIN i[37]
    DIRECTION INPUT ;
    USE SIGNAL ;
    PORT
      LAYER M5 ;
        RECT  2.832 23.676 2.856 23.76 ;
    END
  END i[37]
  PIN i[38]
    DIRECTION INPUT ;
    USE SIGNAL ;
    PORT
      LAYER M5 ;
        RECT  2.928 23.676 2.952 23.76 ;
    END
  END i[38]
  PIN i[39]
    DIRECTION INPUT ;
    USE SIGNAL ;
    PORT
      LAYER M5 ;
        RECT  3.024 23.676 3.048 23.76 ;
    END
  END i[39]
  PIN i[3]
    DIRECTION INPUT ;
    USE SIGNAL ;
    PORT
      LAYER M5 ;
        RECT  18.768 23.676 18.792 23.76 ;
    END
  END i[3]
  PIN i[40]
    DIRECTION INPUT ;
    USE SIGNAL ;
    PORT
      LAYER M5 ;
        RECT  3.12 23.676 3.144 23.76 ;
    END
  END i[40]
  PIN i[41]
    DIRECTION INPUT ;
    USE SIGNAL ;
    PORT
      LAYER M5 ;
        RECT  3.216 23.676 3.24 23.76 ;
    END
  END i[41]
  PIN i[42]
    DIRECTION INPUT ;
    USE SIGNAL ;
    PORT
      LAYER M5 ;
        RECT  3.312 23.676 3.336 23.76 ;
    END
  END i[42]
  PIN i[43]
    DIRECTION INPUT ;
    USE SIGNAL ;
    PORT
      LAYER M5 ;
        RECT  3.408 23.676 3.432 23.76 ;
    END
  END i[43]
  PIN i[44]
    DIRECTION INPUT ;
    USE SIGNAL ;
    PORT
      LAYER M5 ;
        RECT  3.504 23.676 3.528 23.76 ;
    END
  END i[44]
  PIN i[45]
    DIRECTION INPUT ;
    USE SIGNAL ;
    PORT
      LAYER M5 ;
        RECT  3.6 23.676 3.624 23.76 ;
    END
  END i[45]
  PIN i[46]
    DIRECTION INPUT ;
    USE SIGNAL ;
    PORT
      LAYER M5 ;
        RECT  3.696 23.676 3.72 23.76 ;
    END
  END i[46]
  PIN i[47]
    DIRECTION INPUT ;
    USE SIGNAL ;
    PORT
      LAYER M5 ;
        RECT  3.792 23.676 3.816 23.76 ;
    END
  END i[47]
  PIN i[48]
    DIRECTION INPUT ;
    USE SIGNAL ;
    PORT
      LAYER M5 ;
        RECT  3.888 23.676 3.912 23.76 ;
    END
  END i[48]
  PIN i[49]
    DIRECTION INPUT ;
    USE SIGNAL ;
    PORT
      LAYER M5 ;
        RECT  3.984 23.676 4.008 23.76 ;
    END
  END i[49]
  PIN i[4]
    DIRECTION INPUT ;
    USE SIGNAL ;
    PORT
      LAYER M5 ;
        RECT  18.864 23.676 18.888 23.76 ;
    END
  END i[4]
  PIN i[50]
    DIRECTION INPUT ;
    USE SIGNAL ;
    PORT
      LAYER M5 ;
        RECT  4.08 23.676 4.104 23.76 ;
    END
  END i[50]
  PIN i[51]
    DIRECTION INPUT ;
    USE SIGNAL ;
    PORT
      LAYER M5 ;
        RECT  4.176 23.676 4.2 23.76 ;
    END
  END i[51]
  PIN i[52]
    DIRECTION INPUT ;
    USE SIGNAL ;
    PORT
      LAYER M5 ;
        RECT  4.272 23.676 4.296 23.76 ;
    END
  END i[52]
  PIN i[53]
    DIRECTION INPUT ;
    USE SIGNAL ;
    PORT
      LAYER M5 ;
        RECT  4.368 23.676 4.392 23.76 ;
    END
  END i[53]
  PIN i[54]
    DIRECTION INPUT ;
    USE SIGNAL ;
    PORT
      LAYER M5 ;
        RECT  4.464 23.676 4.488 23.76 ;
    END
  END i[54]
  PIN i[55]
    DIRECTION INPUT ;
    USE SIGNAL ;
    PORT
      LAYER M5 ;
        RECT  4.56 23.676 4.584 23.76 ;
    END
  END i[55]
  PIN i[56]
    DIRECTION INPUT ;
    USE SIGNAL ;
    PORT
      LAYER M5 ;
        RECT  4.656 23.676 4.68 23.76 ;
    END
  END i[56]
  PIN i[57]
    DIRECTION INPUT ;
    USE SIGNAL ;
    PORT
      LAYER M5 ;
        RECT  4.752 23.676 4.776 23.76 ;
    END
  END i[57]
  PIN i[58]
    DIRECTION INPUT ;
    USE SIGNAL ;
    PORT
      LAYER M5 ;
        RECT  4.848 23.676 4.872 23.76 ;
    END
  END i[58]
  PIN i[59]
    DIRECTION INPUT ;
    USE SIGNAL ;
    PORT
      LAYER M5 ;
        RECT  4.944 23.676 4.968 23.76 ;
    END
  END i[59]
  PIN i[5]
    DIRECTION INPUT ;
    USE SIGNAL ;
    PORT
      LAYER M5 ;
        RECT  18.96 23.676 18.984 23.76 ;
    END
  END i[5]
  PIN i[60]
    DIRECTION INPUT ;
    USE SIGNAL ;
    PORT
      LAYER M5 ;
        RECT  5.04 23.676 5.064 23.76 ;
    END
  END i[60]
  PIN i[61]
    DIRECTION INPUT ;
    USE SIGNAL ;
    PORT
      LAYER M5 ;
        RECT  5.136 23.676 5.16 23.76 ;
    END
  END i[61]
  PIN i[62]
    DIRECTION INPUT ;
    USE SIGNAL ;
    PORT
      LAYER M5 ;
        RECT  5.232 23.676 5.256 23.76 ;
    END
  END i[62]
  PIN i[63]
    DIRECTION INPUT ;
    USE SIGNAL ;
    PORT
      LAYER M5 ;
        RECT  5.328 23.676 5.352 23.76 ;
    END
  END i[63]
  PIN i[64]
    DIRECTION INPUT ;
    USE SIGNAL ;
    PORT
      LAYER M5 ;
        RECT  5.424 23.676 5.448 23.76 ;
    END
  END i[64]
  PIN i[65]
    DIRECTION INPUT ;
    USE SIGNAL ;
    PORT
      LAYER M5 ;
        RECT  5.52 23.676 5.544 23.76 ;
    END
  END i[65]
  PIN i[66]
    DIRECTION INPUT ;
    USE SIGNAL ;
    PORT
      LAYER M5 ;
        RECT  5.616 23.676 5.64 23.76 ;
    END
  END i[66]
  PIN i[67]
    DIRECTION INPUT ;
    USE SIGNAL ;
    PORT
      LAYER M5 ;
        RECT  5.712 23.676 5.736 23.76 ;
    END
  END i[67]
  PIN i[68]
    DIRECTION INPUT ;
    USE SIGNAL ;
    PORT
      LAYER M5 ;
        RECT  5.808 23.676 5.832 23.76 ;
    END
  END i[68]
  PIN i[69]
    DIRECTION INPUT ;
    USE SIGNAL ;
    PORT
      LAYER M5 ;
        RECT  5.904 23.676 5.928 23.76 ;
    END
  END i[69]
  PIN i[6]
    DIRECTION INPUT ;
    USE SIGNAL ;
    PORT
      LAYER M5 ;
        RECT  19.056 23.676 19.08 23.76 ;
    END
  END i[6]
  PIN i[70]
    DIRECTION INPUT ;
    USE SIGNAL ;
    PORT
      LAYER M5 ;
        RECT  6 23.676 6.024 23.76 ;
    END
  END i[70]
  PIN i[71]
    DIRECTION INPUT ;
    USE SIGNAL ;
    PORT
      LAYER M5 ;
        RECT  6.096 23.676 6.12 23.76 ;
    END
  END i[71]
  PIN i[72]
    DIRECTION INPUT ;
    USE SIGNAL ;
    PORT
      LAYER M5 ;
        RECT  6.192 23.676 6.216 23.76 ;
    END
  END i[72]
  PIN i[73]
    DIRECTION INPUT ;
    USE SIGNAL ;
    PORT
      LAYER M5 ;
        RECT  6.288 23.676 6.312 23.76 ;
    END
  END i[73]
  PIN i[74]
    DIRECTION INPUT ;
    USE SIGNAL ;
    PORT
      LAYER M5 ;
        RECT  6.384 23.676 6.408 23.76 ;
    END
  END i[74]
  PIN i[75]
    DIRECTION INPUT ;
    USE SIGNAL ;
    PORT
      LAYER M5 ;
        RECT  6.48 23.676 6.504 23.76 ;
    END
  END i[75]
  PIN i[76]
    DIRECTION INPUT ;
    USE SIGNAL ;
    PORT
      LAYER M5 ;
        RECT  6.576 23.676 6.6 23.76 ;
    END
  END i[76]
  PIN i[77]
    DIRECTION INPUT ;
    USE SIGNAL ;
    PORT
      LAYER M5 ;
        RECT  6.672 23.676 6.696 23.76 ;
    END
  END i[77]
  PIN i[78]
    DIRECTION INPUT ;
    USE SIGNAL ;
    PORT
      LAYER M5 ;
        RECT  6.768 23.676 6.792 23.76 ;
    END
  END i[78]
  PIN i[79]
    DIRECTION INPUT ;
    USE SIGNAL ;
    PORT
      LAYER M5 ;
        RECT  6.864 23.676 6.888 23.76 ;
    END
  END i[79]
  PIN i[7]
    DIRECTION INPUT ;
    USE SIGNAL ;
    PORT
      LAYER M5 ;
        RECT  19.152 23.676 19.176 23.76 ;
    END
  END i[7]
  PIN i[80]
    DIRECTION INPUT ;
    USE SIGNAL ;
    PORT
      LAYER M5 ;
        RECT  6.96 23.676 6.984 23.76 ;
    END
  END i[80]
  PIN i[81]
    DIRECTION INPUT ;
    USE SIGNAL ;
    PORT
      LAYER M5 ;
        RECT  7.056 23.676 7.08 23.76 ;
    END
  END i[81]
  PIN i[82]
    DIRECTION INPUT ;
    USE SIGNAL ;
    PORT
      LAYER M5 ;
        RECT  7.152 23.676 7.176 23.76 ;
    END
  END i[82]
  PIN i[83]
    DIRECTION INPUT ;
    USE SIGNAL ;
    PORT
      LAYER M5 ;
        RECT  7.248 23.676 7.272 23.76 ;
    END
  END i[83]
  PIN i[84]
    DIRECTION INPUT ;
    USE SIGNAL ;
    PORT
      LAYER M5 ;
        RECT  7.344 23.676 7.368 23.76 ;
    END
  END i[84]
  PIN i[85]
    DIRECTION INPUT ;
    USE SIGNAL ;
    PORT
      LAYER M5 ;
        RECT  7.44 23.676 7.464 23.76 ;
    END
  END i[85]
  PIN i[86]
    DIRECTION INPUT ;
    USE SIGNAL ;
    PORT
      LAYER M5 ;
        RECT  7.536 23.676 7.56 23.76 ;
    END
  END i[86]
  PIN i[87]
    DIRECTION INPUT ;
    USE SIGNAL ;
    PORT
      LAYER M5 ;
        RECT  7.632 23.676 7.656 23.76 ;
    END
  END i[87]
  PIN i[88]
    DIRECTION INPUT ;
    USE SIGNAL ;
    PORT
      LAYER M5 ;
        RECT  7.728 23.676 7.752 23.76 ;
    END
  END i[88]
  PIN i[89]
    DIRECTION INPUT ;
    USE SIGNAL ;
    PORT
      LAYER M5 ;
        RECT  7.824 23.676 7.848 23.76 ;
    END
  END i[89]
  PIN i[8]
    DIRECTION INPUT ;
    USE SIGNAL ;
    PORT
      LAYER M5 ;
        RECT  19.248 23.676 19.272 23.76 ;
    END
  END i[8]
  PIN i[90]
    DIRECTION INPUT ;
    USE SIGNAL ;
    PORT
      LAYER M5 ;
        RECT  7.92 23.676 7.944 23.76 ;
    END
  END i[90]
  PIN i[91]
    DIRECTION INPUT ;
    USE SIGNAL ;
    PORT
      LAYER M5 ;
        RECT  8.016 23.676 8.04 23.76 ;
    END
  END i[91]
  PIN i[92]
    DIRECTION INPUT ;
    USE SIGNAL ;
    PORT
      LAYER M5 ;
        RECT  8.112 23.676 8.136 23.76 ;
    END
  END i[92]
  PIN i[93]
    DIRECTION INPUT ;
    USE SIGNAL ;
    PORT
      LAYER M5 ;
        RECT  8.208 23.676 8.232 23.76 ;
    END
  END i[93]
  PIN i[94]
    DIRECTION INPUT ;
    USE SIGNAL ;
    PORT
      LAYER M5 ;
        RECT  8.304 23.676 8.328 23.76 ;
    END
  END i[94]
  PIN i[95]
    DIRECTION INPUT ;
    USE SIGNAL ;
    PORT
      LAYER M5 ;
        RECT  8.4 23.676 8.424 23.76 ;
    END
  END i[95]
  PIN i[96]
    DIRECTION INPUT ;
    USE SIGNAL ;
    PORT
      LAYER M5 ;
        RECT  8.496 23.676 8.52 23.76 ;
    END
  END i[96]
  PIN i[97]
    DIRECTION INPUT ;
    USE SIGNAL ;
    PORT
      LAYER M5 ;
        RECT  8.592 23.676 8.616 23.76 ;
    END
  END i[97]
  PIN i[98]
    DIRECTION INPUT ;
    USE SIGNAL ;
    PORT
      LAYER M5 ;
        RECT  8.688 23.676 8.712 23.76 ;
    END
  END i[98]
  PIN i[99]
    DIRECTION INPUT ;
    USE SIGNAL ;
    PORT
      LAYER M5 ;
        RECT  8.784 23.676 8.808 23.76 ;
    END
  END i[99]
  PIN i[9]
    DIRECTION INPUT ;
    USE SIGNAL ;
    PORT
      LAYER M5 ;
        RECT  19.344 23.676 19.368 23.76 ;
    END
  END i[9]
  PIN o[0]
    DIRECTION OUTPUT ;
    USE SIGNAL ;
    PORT
      LAYER M5 ;
        RECT  13.008 0 13.032 0.084 ;
    END
  END o[0]
  PIN o[100]
    DIRECTION OUTPUT ;
    USE SIGNAL ;
    PORT
      LAYER M5 ;
        RECT  7.248 0 7.272 0.084 ;
    END
  END o[100]
  PIN o[101]
    DIRECTION OUTPUT ;
    USE SIGNAL ;
    PORT
      LAYER M5 ;
        RECT  7.344 0 7.368 0.084 ;
    END
  END o[101]
  PIN o[102]
    DIRECTION OUTPUT ;
    USE SIGNAL ;
    PORT
      LAYER M5 ;
        RECT  7.44 0 7.464 0.084 ;
    END
  END o[102]
  PIN o[103]
    DIRECTION OUTPUT ;
    USE SIGNAL ;
    PORT
      LAYER M5 ;
        RECT  7.536 0 7.56 0.084 ;
    END
  END o[103]
  PIN o[104]
    DIRECTION OUTPUT ;
    USE SIGNAL ;
    PORT
      LAYER M5 ;
        RECT  7.632 0 7.656 0.084 ;
    END
  END o[104]
  PIN o[105]
    DIRECTION OUTPUT ;
    USE SIGNAL ;
    PORT
      LAYER M5 ;
        RECT  7.728 0 7.752 0.084 ;
    END
  END o[105]
  PIN o[106]
    DIRECTION OUTPUT ;
    USE SIGNAL ;
    PORT
      LAYER M5 ;
        RECT  7.824 0 7.848 0.084 ;
    END
  END o[106]
  PIN o[107]
    DIRECTION OUTPUT ;
    USE SIGNAL ;
    PORT
      LAYER M5 ;
        RECT  7.92 0 7.944 0.084 ;
    END
  END o[107]
  PIN o[108]
    DIRECTION OUTPUT ;
    USE SIGNAL ;
    PORT
      LAYER M5 ;
        RECT  8.016 0 8.04 0.084 ;
    END
  END o[108]
  PIN o[109]
    DIRECTION OUTPUT ;
    USE SIGNAL ;
    PORT
      LAYER M5 ;
        RECT  8.112 0 8.136 0.084 ;
    END
  END o[109]
  PIN o[10]
    DIRECTION OUTPUT ;
    USE SIGNAL ;
    PORT
      LAYER M5 ;
        RECT  13.968 0 13.992 0.084 ;
    END
  END o[10]
  PIN o[110]
    DIRECTION OUTPUT ;
    USE SIGNAL ;
    PORT
      LAYER M5 ;
        RECT  8.208 0 8.232 0.084 ;
    END
  END o[110]
  PIN o[111]
    DIRECTION OUTPUT ;
    USE SIGNAL ;
    PORT
      LAYER M5 ;
        RECT  8.304 0 8.328 0.084 ;
    END
  END o[111]
  PIN o[112]
    DIRECTION OUTPUT ;
    USE SIGNAL ;
    PORT
      LAYER M5 ;
        RECT  8.4 0 8.424 0.084 ;
    END
  END o[112]
  PIN o[113]
    DIRECTION OUTPUT ;
    USE SIGNAL ;
    PORT
      LAYER M5 ;
        RECT  8.496 0 8.52 0.084 ;
    END
  END o[113]
  PIN o[114]
    DIRECTION OUTPUT ;
    USE SIGNAL ;
    PORT
      LAYER M5 ;
        RECT  8.592 0 8.616 0.084 ;
    END
  END o[114]
  PIN o[115]
    DIRECTION OUTPUT ;
    USE SIGNAL ;
    PORT
      LAYER M5 ;
        RECT  8.688 0 8.712 0.084 ;
    END
  END o[115]
  PIN o[116]
    DIRECTION OUTPUT ;
    USE SIGNAL ;
    PORT
      LAYER M5 ;
        RECT  8.784 0 8.808 0.084 ;
    END
  END o[116]
  PIN o[117]
    DIRECTION OUTPUT ;
    USE SIGNAL ;
    PORT
      LAYER M5 ;
        RECT  8.88 0 8.904 0.084 ;
    END
  END o[117]
  PIN o[118]
    DIRECTION OUTPUT ;
    USE SIGNAL ;
    PORT
      LAYER M5 ;
        RECT  8.976 0 9 0.084 ;
    END
  END o[118]
  PIN o[119]
    DIRECTION OUTPUT ;
    USE SIGNAL ;
    PORT
      LAYER M5 ;
        RECT  9.072 0 9.096 0.084 ;
    END
  END o[119]
  PIN o[11]
    DIRECTION OUTPUT ;
    USE SIGNAL ;
    PORT
      LAYER M5 ;
        RECT  14.064 0 14.088 0.084 ;
    END
  END o[11]
  PIN o[120]
    DIRECTION OUTPUT ;
    USE SIGNAL ;
    PORT
      LAYER M5 ;
        RECT  9.168 0 9.192 0.084 ;
    END
  END o[120]
  PIN o[121]
    DIRECTION OUTPUT ;
    USE SIGNAL ;
    PORT
      LAYER M5 ;
        RECT  9.264 0 9.288 0.084 ;
    END
  END o[121]
  PIN o[122]
    DIRECTION OUTPUT ;
    USE SIGNAL ;
    PORT
      LAYER M5 ;
        RECT  9.36 0 9.384 0.084 ;
    END
  END o[122]
  PIN o[123]
    DIRECTION OUTPUT ;
    USE SIGNAL ;
    PORT
      LAYER M5 ;
        RECT  9.456 0 9.48 0.084 ;
    END
  END o[123]
  PIN o[124]
    DIRECTION OUTPUT ;
    USE SIGNAL ;
    PORT
      LAYER M5 ;
        RECT  9.552 0 9.576 0.084 ;
    END
  END o[124]
  PIN o[125]
    DIRECTION OUTPUT ;
    USE SIGNAL ;
    PORT
      LAYER M5 ;
        RECT  9.648 0 9.672 0.084 ;
    END
  END o[125]
  PIN o[126]
    DIRECTION OUTPUT ;
    USE SIGNAL ;
    PORT
      LAYER M5 ;
        RECT  9.744 0 9.768 0.084 ;
    END
  END o[126]
  PIN o[127]
    DIRECTION OUTPUT ;
    USE SIGNAL ;
    PORT
      LAYER M5 ;
        RECT  9.84 0 9.864 0.084 ;
    END
  END o[127]
  PIN o[128]
    DIRECTION OUTPUT ;
    USE SIGNAL ;
    PORT
      LAYER M5 ;
        RECT  22.992 0 23.016 0.084 ;
    END
  END o[128]
  PIN o[129]
    DIRECTION OUTPUT ;
    USE SIGNAL ;
    PORT
      LAYER M5 ;
        RECT  23.088 0 23.112 0.084 ;
    END
  END o[129]
  PIN o[12]
    DIRECTION OUTPUT ;
    USE SIGNAL ;
    PORT
      LAYER M5 ;
        RECT  14.16 0 14.184 0.084 ;
    END
  END o[12]
  PIN o[130]
    DIRECTION OUTPUT ;
    USE SIGNAL ;
    PORT
      LAYER M5 ;
        RECT  23.184 0 23.208 0.084 ;
    END
  END o[130]
  PIN o[131]
    DIRECTION OUTPUT ;
    USE SIGNAL ;
    PORT
      LAYER M5 ;
        RECT  23.28 0 23.304 0.084 ;
    END
  END o[131]
  PIN o[132]
    DIRECTION OUTPUT ;
    USE SIGNAL ;
    PORT
      LAYER M5 ;
        RECT  23.376 0 23.4 0.084 ;
    END
  END o[132]
  PIN o[133]
    DIRECTION OUTPUT ;
    USE SIGNAL ;
    PORT
      LAYER M5 ;
        RECT  23.472 0 23.496 0.084 ;
    END
  END o[133]
  PIN o[134]
    DIRECTION OUTPUT ;
    USE SIGNAL ;
    PORT
      LAYER M5 ;
        RECT  23.568 0 23.592 0.084 ;
    END
  END o[134]
  PIN o[135]
    DIRECTION OUTPUT ;
    USE SIGNAL ;
    PORT
      LAYER M5 ;
        RECT  23.664 0 23.688 0.084 ;
    END
  END o[135]
  PIN o[136]
    DIRECTION OUTPUT ;
    USE SIGNAL ;
    PORT
      LAYER M5 ;
        RECT  23.76 0 23.784 0.084 ;
    END
  END o[136]
  PIN o[137]
    DIRECTION OUTPUT ;
    USE SIGNAL ;
    PORT
      LAYER M5 ;
        RECT  23.856 0 23.88 0.084 ;
    END
  END o[137]
  PIN o[138]
    DIRECTION OUTPUT ;
    USE SIGNAL ;
    PORT
      LAYER M5 ;
        RECT  23.952 0 23.976 0.084 ;
    END
  END o[138]
  PIN o[139]
    DIRECTION OUTPUT ;
    USE SIGNAL ;
    PORT
      LAYER M5 ;
        RECT  24.048 0 24.072 0.084 ;
    END
  END o[139]
  PIN o[13]
    DIRECTION OUTPUT ;
    USE SIGNAL ;
    PORT
      LAYER M5 ;
        RECT  14.256 0 14.28 0.084 ;
    END
  END o[13]
  PIN o[140]
    DIRECTION OUTPUT ;
    USE SIGNAL ;
    PORT
      LAYER M5 ;
        RECT  24.144 0 24.168 0.084 ;
    END
  END o[140]
  PIN o[141]
    DIRECTION OUTPUT ;
    USE SIGNAL ;
    PORT
      LAYER M5 ;
        RECT  24.24 0 24.264 0.084 ;
    END
  END o[141]
  PIN o[142]
    DIRECTION OUTPUT ;
    USE SIGNAL ;
    PORT
      LAYER M5 ;
        RECT  24.336 0 24.36 0.084 ;
    END
  END o[142]
  PIN o[143]
    DIRECTION OUTPUT ;
    USE SIGNAL ;
    PORT
      LAYER M5 ;
        RECT  24.432 0 24.456 0.084 ;
    END
  END o[143]
  PIN o[144]
    DIRECTION OUTPUT ;
    USE SIGNAL ;
    PORT
      LAYER M5 ;
        RECT  24.528 0 24.552 0.084 ;
    END
  END o[144]
  PIN o[145]
    DIRECTION OUTPUT ;
    USE SIGNAL ;
    PORT
      LAYER M5 ;
        RECT  24.624 0 24.648 0.084 ;
    END
  END o[145]
  PIN o[146]
    DIRECTION OUTPUT ;
    USE SIGNAL ;
    PORT
      LAYER M5 ;
        RECT  24.72 0 24.744 0.084 ;
    END
  END o[146]
  PIN o[147]
    DIRECTION OUTPUT ;
    USE SIGNAL ;
    PORT
      LAYER M5 ;
        RECT  24.816 0 24.84 0.084 ;
    END
  END o[147]
  PIN o[148]
    DIRECTION OUTPUT ;
    USE SIGNAL ;
    PORT
      LAYER M5 ;
        RECT  24.912 0 24.936 0.084 ;
    END
  END o[148]
  PIN o[149]
    DIRECTION OUTPUT ;
    USE SIGNAL ;
    PORT
      LAYER M5 ;
        RECT  25.008 0 25.032 0.084 ;
    END
  END o[149]
  PIN o[14]
    DIRECTION OUTPUT ;
    USE SIGNAL ;
    PORT
      LAYER M5 ;
        RECT  14.352 0 14.376 0.084 ;
    END
  END o[14]
  PIN o[150]
    DIRECTION OUTPUT ;
    USE SIGNAL ;
    PORT
      LAYER M5 ;
        RECT  25.104 0 25.128 0.084 ;
    END
  END o[150]
  PIN o[151]
    DIRECTION OUTPUT ;
    USE SIGNAL ;
    PORT
      LAYER M5 ;
        RECT  25.2 0 25.224 0.084 ;
    END
  END o[151]
  PIN o[152]
    DIRECTION OUTPUT ;
    USE SIGNAL ;
    PORT
      LAYER M5 ;
        RECT  25.296 0 25.32 0.084 ;
    END
  END o[152]
  PIN o[153]
    DIRECTION OUTPUT ;
    USE SIGNAL ;
    PORT
      LAYER M5 ;
        RECT  25.392 0 25.416 0.084 ;
    END
  END o[153]
  PIN o[154]
    DIRECTION OUTPUT ;
    USE SIGNAL ;
    PORT
      LAYER M5 ;
        RECT  25.488 0 25.512 0.084 ;
    END
  END o[154]
  PIN o[155]
    DIRECTION OUTPUT ;
    USE SIGNAL ;
    PORT
      LAYER M5 ;
        RECT  25.584 0 25.608 0.084 ;
    END
  END o[155]
  PIN o[156]
    DIRECTION OUTPUT ;
    USE SIGNAL ;
    PORT
      LAYER M5 ;
        RECT  25.68 0 25.704 0.084 ;
    END
  END o[156]
  PIN o[157]
    DIRECTION OUTPUT ;
    USE SIGNAL ;
    PORT
      LAYER M5 ;
        RECT  25.776 0 25.8 0.084 ;
    END
  END o[157]
  PIN o[158]
    DIRECTION OUTPUT ;
    USE SIGNAL ;
    PORT
      LAYER M5 ;
        RECT  25.872 0 25.896 0.084 ;
    END
  END o[158]
  PIN o[159]
    DIRECTION OUTPUT ;
    USE SIGNAL ;
    PORT
      LAYER M5 ;
        RECT  25.968 0 25.992 0.084 ;
    END
  END o[159]
  PIN o[15]
    DIRECTION OUTPUT ;
    USE SIGNAL ;
    PORT
      LAYER M5 ;
        RECT  14.448 0 14.472 0.084 ;
    END
  END o[15]
  PIN o[160]
    DIRECTION OUTPUT ;
    USE SIGNAL ;
    PORT
      LAYER M5 ;
        RECT  16.08 0 16.104 0.084 ;
    END
  END o[160]
  PIN o[161]
    DIRECTION OUTPUT ;
    USE SIGNAL ;
    PORT
      LAYER M5 ;
        RECT  16.176 0 16.2 0.084 ;
    END
  END o[161]
  PIN o[162]
    DIRECTION OUTPUT ;
    USE SIGNAL ;
    PORT
      LAYER M5 ;
        RECT  16.272 0 16.296 0.084 ;
    END
  END o[162]
  PIN o[163]
    DIRECTION OUTPUT ;
    USE SIGNAL ;
    PORT
      LAYER M5 ;
        RECT  16.368 0 16.392 0.084 ;
    END
  END o[163]
  PIN o[164]
    DIRECTION OUTPUT ;
    USE SIGNAL ;
    PORT
      LAYER M5 ;
        RECT  16.464 0 16.488 0.084 ;
    END
  END o[164]
  PIN o[165]
    DIRECTION OUTPUT ;
    USE SIGNAL ;
    PORT
      LAYER M5 ;
        RECT  16.56 0 16.584 0.084 ;
    END
  END o[165]
  PIN o[166]
    DIRECTION OUTPUT ;
    USE SIGNAL ;
    PORT
      LAYER M5 ;
        RECT  16.656 0 16.68 0.084 ;
    END
  END o[166]
  PIN o[167]
    DIRECTION OUTPUT ;
    USE SIGNAL ;
    PORT
      LAYER M5 ;
        RECT  16.752 0 16.776 0.084 ;
    END
  END o[167]
  PIN o[168]
    DIRECTION OUTPUT ;
    USE SIGNAL ;
    PORT
      LAYER M5 ;
        RECT  16.848 0 16.872 0.084 ;
    END
  END o[168]
  PIN o[169]
    DIRECTION OUTPUT ;
    USE SIGNAL ;
    PORT
      LAYER M5 ;
        RECT  16.944 0 16.968 0.084 ;
    END
  END o[169]
  PIN o[16]
    DIRECTION OUTPUT ;
    USE SIGNAL ;
    PORT
      LAYER M5 ;
        RECT  14.544 0 14.568 0.084 ;
    END
  END o[16]
  PIN o[170]
    DIRECTION OUTPUT ;
    USE SIGNAL ;
    PORT
      LAYER M5 ;
        RECT  17.04 0 17.064 0.084 ;
    END
  END o[170]
  PIN o[171]
    DIRECTION OUTPUT ;
    USE SIGNAL ;
    PORT
      LAYER M5 ;
        RECT  17.136 0 17.16 0.084 ;
    END
  END o[171]
  PIN o[172]
    DIRECTION OUTPUT ;
    USE SIGNAL ;
    PORT
      LAYER M5 ;
        RECT  17.232 0 17.256 0.084 ;
    END
  END o[172]
  PIN o[173]
    DIRECTION OUTPUT ;
    USE SIGNAL ;
    PORT
      LAYER M5 ;
        RECT  17.328 0 17.352 0.084 ;
    END
  END o[173]
  PIN o[174]
    DIRECTION OUTPUT ;
    USE SIGNAL ;
    PORT
      LAYER M5 ;
        RECT  17.424 0 17.448 0.084 ;
    END
  END o[174]
  PIN o[175]
    DIRECTION OUTPUT ;
    USE SIGNAL ;
    PORT
      LAYER M5 ;
        RECT  17.52 0 17.544 0.084 ;
    END
  END o[175]
  PIN o[176]
    DIRECTION OUTPUT ;
    USE SIGNAL ;
    PORT
      LAYER M5 ;
        RECT  17.616 0 17.64 0.084 ;
    END
  END o[176]
  PIN o[177]
    DIRECTION OUTPUT ;
    USE SIGNAL ;
    PORT
      LAYER M5 ;
        RECT  17.712 0 17.736 0.084 ;
    END
  END o[177]
  PIN o[178]
    DIRECTION OUTPUT ;
    USE SIGNAL ;
    PORT
      LAYER M5 ;
        RECT  17.808 0 17.832 0.084 ;
    END
  END o[178]
  PIN o[179]
    DIRECTION OUTPUT ;
    USE SIGNAL ;
    PORT
      LAYER M5 ;
        RECT  17.904 0 17.928 0.084 ;
    END
  END o[179]
  PIN o[17]
    DIRECTION OUTPUT ;
    USE SIGNAL ;
    PORT
      LAYER M5 ;
        RECT  14.64 0 14.664 0.084 ;
    END
  END o[17]
  PIN o[180]
    DIRECTION OUTPUT ;
    USE SIGNAL ;
    PORT
      LAYER M5 ;
        RECT  18 0 18.024 0.084 ;
    END
  END o[180]
  PIN o[181]
    DIRECTION OUTPUT ;
    USE SIGNAL ;
    PORT
      LAYER M5 ;
        RECT  18.096 0 18.12 0.084 ;
    END
  END o[181]
  PIN o[182]
    DIRECTION OUTPUT ;
    USE SIGNAL ;
    PORT
      LAYER M5 ;
        RECT  18.192 0 18.216 0.084 ;
    END
  END o[182]
  PIN o[183]
    DIRECTION OUTPUT ;
    USE SIGNAL ;
    PORT
      LAYER M5 ;
        RECT  18.288 0 18.312 0.084 ;
    END
  END o[183]
  PIN o[184]
    DIRECTION OUTPUT ;
    USE SIGNAL ;
    PORT
      LAYER M5 ;
        RECT  18.384 0 18.408 0.084 ;
    END
  END o[184]
  PIN o[185]
    DIRECTION OUTPUT ;
    USE SIGNAL ;
    PORT
      LAYER M5 ;
        RECT  18.48 0 18.504 0.084 ;
    END
  END o[185]
  PIN o[186]
    DIRECTION OUTPUT ;
    USE SIGNAL ;
    PORT
      LAYER M5 ;
        RECT  18.576 0 18.6 0.084 ;
    END
  END o[186]
  PIN o[187]
    DIRECTION OUTPUT ;
    USE SIGNAL ;
    PORT
      LAYER M5 ;
        RECT  18.672 0 18.696 0.084 ;
    END
  END o[187]
  PIN o[188]
    DIRECTION OUTPUT ;
    USE SIGNAL ;
    PORT
      LAYER M5 ;
        RECT  18.768 0 18.792 0.084 ;
    END
  END o[188]
  PIN o[189]
    DIRECTION OUTPUT ;
    USE SIGNAL ;
    PORT
      LAYER M5 ;
        RECT  18.864 0 18.888 0.084 ;
    END
  END o[189]
  PIN o[18]
    DIRECTION OUTPUT ;
    USE SIGNAL ;
    PORT
      LAYER M5 ;
        RECT  14.736 0 14.76 0.084 ;
    END
  END o[18]
  PIN o[190]
    DIRECTION OUTPUT ;
    USE SIGNAL ;
    PORT
      LAYER M5 ;
        RECT  18.96 0 18.984 0.084 ;
    END
  END o[190]
  PIN o[191]
    DIRECTION OUTPUT ;
    USE SIGNAL ;
    PORT
      LAYER M5 ;
        RECT  19.056 0 19.08 0.084 ;
    END
  END o[191]
  PIN o[192]
    DIRECTION OUTPUT ;
    USE SIGNAL ;
    PORT
      LAYER M5 ;
        RECT  9.936 0 9.96 0.084 ;
    END
  END o[192]
  PIN o[193]
    DIRECTION OUTPUT ;
    USE SIGNAL ;
    PORT
      LAYER M5 ;
        RECT  10.032 0 10.056 0.084 ;
    END
  END o[193]
  PIN o[194]
    DIRECTION OUTPUT ;
    USE SIGNAL ;
    PORT
      LAYER M5 ;
        RECT  10.128 0 10.152 0.084 ;
    END
  END o[194]
  PIN o[195]
    DIRECTION OUTPUT ;
    USE SIGNAL ;
    PORT
      LAYER M5 ;
        RECT  10.224 0 10.248 0.084 ;
    END
  END o[195]
  PIN o[196]
    DIRECTION OUTPUT ;
    USE SIGNAL ;
    PORT
      LAYER M5 ;
        RECT  10.32 0 10.344 0.084 ;
    END
  END o[196]
  PIN o[197]
    DIRECTION OUTPUT ;
    USE SIGNAL ;
    PORT
      LAYER M5 ;
        RECT  10.416 0 10.44 0.084 ;
    END
  END o[197]
  PIN o[198]
    DIRECTION OUTPUT ;
    USE SIGNAL ;
    PORT
      LAYER M5 ;
        RECT  10.512 0 10.536 0.084 ;
    END
  END o[198]
  PIN o[199]
    DIRECTION OUTPUT ;
    USE SIGNAL ;
    PORT
      LAYER M5 ;
        RECT  10.608 0 10.632 0.084 ;
    END
  END o[199]
  PIN o[19]
    DIRECTION OUTPUT ;
    USE SIGNAL ;
    PORT
      LAYER M5 ;
        RECT  14.832 0 14.856 0.084 ;
    END
  END o[19]
  PIN o[1]
    DIRECTION OUTPUT ;
    USE SIGNAL ;
    PORT
      LAYER M5 ;
        RECT  13.104 0 13.128 0.084 ;
    END
  END o[1]
  PIN o[200]
    DIRECTION OUTPUT ;
    USE SIGNAL ;
    PORT
      LAYER M5 ;
        RECT  10.704 0 10.728 0.084 ;
    END
  END o[200]
  PIN o[201]
    DIRECTION OUTPUT ;
    USE SIGNAL ;
    PORT
      LAYER M5 ;
        RECT  10.8 0 10.824 0.084 ;
    END
  END o[201]
  PIN o[202]
    DIRECTION OUTPUT ;
    USE SIGNAL ;
    PORT
      LAYER M5 ;
        RECT  10.896 0 10.92 0.084 ;
    END
  END o[202]
  PIN o[203]
    DIRECTION OUTPUT ;
    USE SIGNAL ;
    PORT
      LAYER M5 ;
        RECT  10.992 0 11.016 0.084 ;
    END
  END o[203]
  PIN o[204]
    DIRECTION OUTPUT ;
    USE SIGNAL ;
    PORT
      LAYER M5 ;
        RECT  11.088 0 11.112 0.084 ;
    END
  END o[204]
  PIN o[205]
    DIRECTION OUTPUT ;
    USE SIGNAL ;
    PORT
      LAYER M5 ;
        RECT  11.184 0 11.208 0.084 ;
    END
  END o[205]
  PIN o[206]
    DIRECTION OUTPUT ;
    USE SIGNAL ;
    PORT
      LAYER M5 ;
        RECT  11.28 0 11.304 0.084 ;
    END
  END o[206]
  PIN o[207]
    DIRECTION OUTPUT ;
    USE SIGNAL ;
    PORT
      LAYER M5 ;
        RECT  11.376 0 11.4 0.084 ;
    END
  END o[207]
  PIN o[208]
    DIRECTION OUTPUT ;
    USE SIGNAL ;
    PORT
      LAYER M5 ;
        RECT  11.472 0 11.496 0.084 ;
    END
  END o[208]
  PIN o[209]
    DIRECTION OUTPUT ;
    USE SIGNAL ;
    PORT
      LAYER M5 ;
        RECT  11.568 0 11.592 0.084 ;
    END
  END o[209]
  PIN o[20]
    DIRECTION OUTPUT ;
    USE SIGNAL ;
    PORT
      LAYER M5 ;
        RECT  14.928 0 14.952 0.084 ;
    END
  END o[20]
  PIN o[210]
    DIRECTION OUTPUT ;
    USE SIGNAL ;
    PORT
      LAYER M5 ;
        RECT  11.664 0 11.688 0.084 ;
    END
  END o[210]
  PIN o[211]
    DIRECTION OUTPUT ;
    USE SIGNAL ;
    PORT
      LAYER M5 ;
        RECT  11.76 0 11.784 0.084 ;
    END
  END o[211]
  PIN o[212]
    DIRECTION OUTPUT ;
    USE SIGNAL ;
    PORT
      LAYER M5 ;
        RECT  11.856 0 11.88 0.084 ;
    END
  END o[212]
  PIN o[213]
    DIRECTION OUTPUT ;
    USE SIGNAL ;
    PORT
      LAYER M5 ;
        RECT  11.952 0 11.976 0.084 ;
    END
  END o[213]
  PIN o[214]
    DIRECTION OUTPUT ;
    USE SIGNAL ;
    PORT
      LAYER M5 ;
        RECT  12.048 0 12.072 0.084 ;
    END
  END o[214]
  PIN o[215]
    DIRECTION OUTPUT ;
    USE SIGNAL ;
    PORT
      LAYER M5 ;
        RECT  12.144 0 12.168 0.084 ;
    END
  END o[215]
  PIN o[216]
    DIRECTION OUTPUT ;
    USE SIGNAL ;
    PORT
      LAYER M5 ;
        RECT  12.24 0 12.264 0.084 ;
    END
  END o[216]
  PIN o[217]
    DIRECTION OUTPUT ;
    USE SIGNAL ;
    PORT
      LAYER M5 ;
        RECT  12.336 0 12.36 0.084 ;
    END
  END o[217]
  PIN o[218]
    DIRECTION OUTPUT ;
    USE SIGNAL ;
    PORT
      LAYER M5 ;
        RECT  12.432 0 12.456 0.084 ;
    END
  END o[218]
  PIN o[219]
    DIRECTION OUTPUT ;
    USE SIGNAL ;
    PORT
      LAYER M5 ;
        RECT  12.528 0 12.552 0.084 ;
    END
  END o[219]
  PIN o[21]
    DIRECTION OUTPUT ;
    USE SIGNAL ;
    PORT
      LAYER M5 ;
        RECT  15.024 0 15.048 0.084 ;
    END
  END o[21]
  PIN o[220]
    DIRECTION OUTPUT ;
    USE SIGNAL ;
    PORT
      LAYER M5 ;
        RECT  12.624 0 12.648 0.084 ;
    END
  END o[220]
  PIN o[221]
    DIRECTION OUTPUT ;
    USE SIGNAL ;
    PORT
      LAYER M5 ;
        RECT  12.72 0 12.744 0.084 ;
    END
  END o[221]
  PIN o[222]
    DIRECTION OUTPUT ;
    USE SIGNAL ;
    PORT
      LAYER M5 ;
        RECT  12.816 0 12.84 0.084 ;
    END
  END o[222]
  PIN o[223]
    DIRECTION OUTPUT ;
    USE SIGNAL ;
    PORT
      LAYER M5 ;
        RECT  12.912 0 12.936 0.084 ;
    END
  END o[223]
  PIN o[224]
    DIRECTION OUTPUT ;
    USE SIGNAL ;
    PORT
      LAYER M5 ;
        RECT  19.92 0 19.944 0.084 ;
    END
  END o[224]
  PIN o[225]
    DIRECTION OUTPUT ;
    USE SIGNAL ;
    PORT
      LAYER M5 ;
        RECT  20.016 0 20.04 0.084 ;
    END
  END o[225]
  PIN o[226]
    DIRECTION OUTPUT ;
    USE SIGNAL ;
    PORT
      LAYER M5 ;
        RECT  20.112 0 20.136 0.084 ;
    END
  END o[226]
  PIN o[227]
    DIRECTION OUTPUT ;
    USE SIGNAL ;
    PORT
      LAYER M5 ;
        RECT  20.208 0 20.232 0.084 ;
    END
  END o[227]
  PIN o[228]
    DIRECTION OUTPUT ;
    USE SIGNAL ;
    PORT
      LAYER M5 ;
        RECT  20.304 0 20.328 0.084 ;
    END
  END o[228]
  PIN o[229]
    DIRECTION OUTPUT ;
    USE SIGNAL ;
    PORT
      LAYER M5 ;
        RECT  20.4 0 20.424 0.084 ;
    END
  END o[229]
  PIN o[22]
    DIRECTION OUTPUT ;
    USE SIGNAL ;
    PORT
      LAYER M5 ;
        RECT  15.12 0 15.144 0.084 ;
    END
  END o[22]
  PIN o[230]
    DIRECTION OUTPUT ;
    USE SIGNAL ;
    PORT
      LAYER M5 ;
        RECT  20.496 0 20.52 0.084 ;
    END
  END o[230]
  PIN o[231]
    DIRECTION OUTPUT ;
    USE SIGNAL ;
    PORT
      LAYER M5 ;
        RECT  20.592 0 20.616 0.084 ;
    END
  END o[231]
  PIN o[232]
    DIRECTION OUTPUT ;
    USE SIGNAL ;
    PORT
      LAYER M5 ;
        RECT  20.688 0 20.712 0.084 ;
    END
  END o[232]
  PIN o[233]
    DIRECTION OUTPUT ;
    USE SIGNAL ;
    PORT
      LAYER M5 ;
        RECT  20.784 0 20.808 0.084 ;
    END
  END o[233]
  PIN o[234]
    DIRECTION OUTPUT ;
    USE SIGNAL ;
    PORT
      LAYER M5 ;
        RECT  20.88 0 20.904 0.084 ;
    END
  END o[234]
  PIN o[235]
    DIRECTION OUTPUT ;
    USE SIGNAL ;
    PORT
      LAYER M5 ;
        RECT  20.976 0 21 0.084 ;
    END
  END o[235]
  PIN o[236]
    DIRECTION OUTPUT ;
    USE SIGNAL ;
    PORT
      LAYER M5 ;
        RECT  21.072 0 21.096 0.084 ;
    END
  END o[236]
  PIN o[237]
    DIRECTION OUTPUT ;
    USE SIGNAL ;
    PORT
      LAYER M5 ;
        RECT  21.168 0 21.192 0.084 ;
    END
  END o[237]
  PIN o[238]
    DIRECTION OUTPUT ;
    USE SIGNAL ;
    PORT
      LAYER M5 ;
        RECT  21.264 0 21.288 0.084 ;
    END
  END o[238]
  PIN o[239]
    DIRECTION OUTPUT ;
    USE SIGNAL ;
    PORT
      LAYER M5 ;
        RECT  21.36 0 21.384 0.084 ;
    END
  END o[239]
  PIN o[23]
    DIRECTION OUTPUT ;
    USE SIGNAL ;
    PORT
      LAYER M5 ;
        RECT  15.216 0 15.24 0.084 ;
    END
  END o[23]
  PIN o[240]
    DIRECTION OUTPUT ;
    USE SIGNAL ;
    PORT
      LAYER M5 ;
        RECT  21.456 0 21.48 0.084 ;
    END
  END o[240]
  PIN o[241]
    DIRECTION OUTPUT ;
    USE SIGNAL ;
    PORT
      LAYER M5 ;
        RECT  21.552 0 21.576 0.084 ;
    END
  END o[241]
  PIN o[242]
    DIRECTION OUTPUT ;
    USE SIGNAL ;
    PORT
      LAYER M5 ;
        RECT  21.648 0 21.672 0.084 ;
    END
  END o[242]
  PIN o[243]
    DIRECTION OUTPUT ;
    USE SIGNAL ;
    PORT
      LAYER M5 ;
        RECT  21.744 0 21.768 0.084 ;
    END
  END o[243]
  PIN o[244]
    DIRECTION OUTPUT ;
    USE SIGNAL ;
    PORT
      LAYER M5 ;
        RECT  21.84 0 21.864 0.084 ;
    END
  END o[244]
  PIN o[245]
    DIRECTION OUTPUT ;
    USE SIGNAL ;
    PORT
      LAYER M5 ;
        RECT  21.936 0 21.96 0.084 ;
    END
  END o[245]
  PIN o[246]
    DIRECTION OUTPUT ;
    USE SIGNAL ;
    PORT
      LAYER M5 ;
        RECT  22.032 0 22.056 0.084 ;
    END
  END o[246]
  PIN o[247]
    DIRECTION OUTPUT ;
    USE SIGNAL ;
    PORT
      LAYER M5 ;
        RECT  22.128 0 22.152 0.084 ;
    END
  END o[247]
  PIN o[248]
    DIRECTION OUTPUT ;
    USE SIGNAL ;
    PORT
      LAYER M5 ;
        RECT  22.224 0 22.248 0.084 ;
    END
  END o[248]
  PIN o[249]
    DIRECTION OUTPUT ;
    USE SIGNAL ;
    PORT
      LAYER M5 ;
        RECT  22.32 0 22.344 0.084 ;
    END
  END o[249]
  PIN o[24]
    DIRECTION OUTPUT ;
    USE SIGNAL ;
    PORT
      LAYER M5 ;
        RECT  15.312 0 15.336 0.084 ;
    END
  END o[24]
  PIN o[250]
    DIRECTION OUTPUT ;
    USE SIGNAL ;
    PORT
      LAYER M5 ;
        RECT  22.416 0 22.44 0.084 ;
    END
  END o[250]
  PIN o[251]
    DIRECTION OUTPUT ;
    USE SIGNAL ;
    PORT
      LAYER M5 ;
        RECT  22.512 0 22.536 0.084 ;
    END
  END o[251]
  PIN o[252]
    DIRECTION OUTPUT ;
    USE SIGNAL ;
    PORT
      LAYER M5 ;
        RECT  22.608 0 22.632 0.084 ;
    END
  END o[252]
  PIN o[253]
    DIRECTION OUTPUT ;
    USE SIGNAL ;
    PORT
      LAYER M5 ;
        RECT  22.704 0 22.728 0.084 ;
    END
  END o[253]
  PIN o[254]
    DIRECTION OUTPUT ;
    USE SIGNAL ;
    PORT
      LAYER M5 ;
        RECT  22.8 0 22.824 0.084 ;
    END
  END o[254]
  PIN o[255]
    DIRECTION OUTPUT ;
    USE SIGNAL ;
    PORT
      LAYER M5 ;
        RECT  22.896 0 22.92 0.084 ;
    END
  END o[255]
  PIN o[256]
    DIRECTION OUTPUT ;
    USE SIGNAL ;
    PORT
      LAYER M5 ;
        RECT  26.064 0 26.088 0.084 ;
    END
  END o[256]
  PIN o[257]
    DIRECTION OUTPUT ;
    USE SIGNAL ;
    PORT
      LAYER M5 ;
        RECT  26.16 0 26.184 0.084 ;
    END
  END o[257]
  PIN o[258]
    DIRECTION OUTPUT ;
    USE SIGNAL ;
    PORT
      LAYER M5 ;
        RECT  26.256 0 26.28 0.084 ;
    END
  END o[258]
  PIN o[259]
    DIRECTION OUTPUT ;
    USE SIGNAL ;
    PORT
      LAYER M5 ;
        RECT  26.352 0 26.376 0.084 ;
    END
  END o[259]
  PIN o[25]
    DIRECTION OUTPUT ;
    USE SIGNAL ;
    PORT
      LAYER M5 ;
        RECT  15.408 0 15.432 0.084 ;
    END
  END o[25]
  PIN o[260]
    DIRECTION OUTPUT ;
    USE SIGNAL ;
    PORT
      LAYER M5 ;
        RECT  26.448 0 26.472 0.084 ;
    END
  END o[260]
  PIN o[261]
    DIRECTION OUTPUT ;
    USE SIGNAL ;
    PORT
      LAYER M5 ;
        RECT  26.544 0 26.568 0.084 ;
    END
  END o[261]
  PIN o[262]
    DIRECTION OUTPUT ;
    USE SIGNAL ;
    PORT
      LAYER M5 ;
        RECT  26.64 0 26.664 0.084 ;
    END
  END o[262]
  PIN o[263]
    DIRECTION OUTPUT ;
    USE SIGNAL ;
    PORT
      LAYER M5 ;
        RECT  26.736 0 26.76 0.084 ;
    END
  END o[263]
  PIN o[264]
    DIRECTION OUTPUT ;
    USE SIGNAL ;
    PORT
      LAYER M5 ;
        RECT  26.832 0 26.856 0.084 ;
    END
  END o[264]
  PIN o[265]
    DIRECTION OUTPUT ;
    USE SIGNAL ;
    PORT
      LAYER M5 ;
        RECT  26.928 0 26.952 0.084 ;
    END
  END o[265]
  PIN o[266]
    DIRECTION OUTPUT ;
    USE SIGNAL ;
    PORT
      LAYER M5 ;
        RECT  27.024 0 27.048 0.084 ;
    END
  END o[266]
  PIN o[267]
    DIRECTION OUTPUT ;
    USE SIGNAL ;
    PORT
      LAYER M5 ;
        RECT  27.12 0 27.144 0.084 ;
    END
  END o[267]
  PIN o[268]
    DIRECTION OUTPUT ;
    USE SIGNAL ;
    PORT
      LAYER M5 ;
        RECT  27.216 0 27.24 0.084 ;
    END
  END o[268]
  PIN o[269]
    DIRECTION OUTPUT ;
    USE SIGNAL ;
    PORT
      LAYER M5 ;
        RECT  27.312 0 27.336 0.084 ;
    END
  END o[269]
  PIN o[26]
    DIRECTION OUTPUT ;
    USE SIGNAL ;
    PORT
      LAYER M5 ;
        RECT  15.504 0 15.528 0.084 ;
    END
  END o[26]
  PIN o[270]
    DIRECTION OUTPUT ;
    USE SIGNAL ;
    PORT
      LAYER M5 ;
        RECT  27.408 0 27.432 0.084 ;
    END
  END o[270]
  PIN o[271]
    DIRECTION OUTPUT ;
    USE SIGNAL ;
    PORT
      LAYER M5 ;
        RECT  27.504 0 27.528 0.084 ;
    END
  END o[271]
  PIN o[272]
    DIRECTION OUTPUT ;
    USE SIGNAL ;
    PORT
      LAYER M5 ;
        RECT  27.6 0 27.624 0.084 ;
    END
  END o[272]
  PIN o[273]
    DIRECTION OUTPUT ;
    USE SIGNAL ;
    PORT
      LAYER M5 ;
        RECT  27.696 0 27.72 0.084 ;
    END
  END o[273]
  PIN o[274]
    DIRECTION OUTPUT ;
    USE SIGNAL ;
    PORT
      LAYER M5 ;
        RECT  27.792 0 27.816 0.084 ;
    END
  END o[274]
  PIN o[275]
    DIRECTION OUTPUT ;
    USE SIGNAL ;
    PORT
      LAYER M5 ;
        RECT  27.888 0 27.912 0.084 ;
    END
  END o[275]
  PIN o[276]
    DIRECTION OUTPUT ;
    USE SIGNAL ;
    PORT
      LAYER M5 ;
        RECT  27.984 0 28.008 0.084 ;
    END
  END o[276]
  PIN o[277]
    DIRECTION OUTPUT ;
    USE SIGNAL ;
    PORT
      LAYER M5 ;
        RECT  28.08 0 28.104 0.084 ;
    END
  END o[277]
  PIN o[278]
    DIRECTION OUTPUT ;
    USE SIGNAL ;
    PORT
      LAYER M5 ;
        RECT  28.176 0 28.2 0.084 ;
    END
  END o[278]
  PIN o[279]
    DIRECTION OUTPUT ;
    USE SIGNAL ;
    PORT
      LAYER M5 ;
        RECT  28.272 0 28.296 0.084 ;
    END
  END o[279]
  PIN o[27]
    DIRECTION OUTPUT ;
    USE SIGNAL ;
    PORT
      LAYER M5 ;
        RECT  15.6 0 15.624 0.084 ;
    END
  END o[27]
  PIN o[280]
    DIRECTION OUTPUT ;
    USE SIGNAL ;
    PORT
      LAYER M5 ;
        RECT  28.368 0 28.392 0.084 ;
    END
  END o[280]
  PIN o[281]
    DIRECTION OUTPUT ;
    USE SIGNAL ;
    PORT
      LAYER M5 ;
        RECT  28.464 0 28.488 0.084 ;
    END
  END o[281]
  PIN o[282]
    DIRECTION OUTPUT ;
    USE SIGNAL ;
    PORT
      LAYER M5 ;
        RECT  28.56 0 28.584 0.084 ;
    END
  END o[282]
  PIN o[283]
    DIRECTION OUTPUT ;
    USE SIGNAL ;
    PORT
      LAYER M5 ;
        RECT  28.656 0 28.68 0.084 ;
    END
  END o[283]
  PIN o[284]
    DIRECTION OUTPUT ;
    USE SIGNAL ;
    PORT
      LAYER M5 ;
        RECT  28.752 0 28.776 0.084 ;
    END
  END o[284]
  PIN o[285]
    DIRECTION OUTPUT ;
    USE SIGNAL ;
    PORT
      LAYER M5 ;
        RECT  28.848 0 28.872 0.084 ;
    END
  END o[285]
  PIN o[286]
    DIRECTION OUTPUT ;
    USE SIGNAL ;
    PORT
      LAYER M5 ;
        RECT  28.944 0 28.968 0.084 ;
    END
  END o[286]
  PIN o[287]
    DIRECTION OUTPUT ;
    USE SIGNAL ;
    PORT
      LAYER M5 ;
        RECT  29.04 0 29.064 0.084 ;
    END
  END o[287]
  PIN o[288]
    DIRECTION OUTPUT ;
    USE SIGNAL ;
    PORT
      LAYER M5 ;
        RECT  29.136 0 29.16 0.084 ;
    END
  END o[288]
  PIN o[289]
    DIRECTION OUTPUT ;
    USE SIGNAL ;
    PORT
      LAYER M5 ;
        RECT  29.232 0 29.256 0.084 ;
    END
  END o[289]
  PIN o[28]
    DIRECTION OUTPUT ;
    USE SIGNAL ;
    PORT
      LAYER M5 ;
        RECT  15.696 0 15.72 0.084 ;
    END
  END o[28]
  PIN o[290]
    DIRECTION OUTPUT ;
    USE SIGNAL ;
    PORT
      LAYER M5 ;
        RECT  29.328 0 29.352 0.084 ;
    END
  END o[290]
  PIN o[291]
    DIRECTION OUTPUT ;
    USE SIGNAL ;
    PORT
      LAYER M5 ;
        RECT  29.424 0 29.448 0.084 ;
    END
  END o[291]
  PIN o[292]
    DIRECTION OUTPUT ;
    USE SIGNAL ;
    PORT
      LAYER M5 ;
        RECT  29.52 0 29.544 0.084 ;
    END
  END o[292]
  PIN o[293]
    DIRECTION OUTPUT ;
    USE SIGNAL ;
    PORT
      LAYER M5 ;
        RECT  29.616 0 29.64 0.084 ;
    END
  END o[293]
  PIN o[294]
    DIRECTION OUTPUT ;
    USE SIGNAL ;
    PORT
      LAYER M5 ;
        RECT  29.712 0 29.736 0.084 ;
    END
  END o[294]
  PIN o[295]
    DIRECTION OUTPUT ;
    USE SIGNAL ;
    PORT
      LAYER M5 ;
        RECT  29.808 0 29.832 0.084 ;
    END
  END o[295]
  PIN o[296]
    DIRECTION OUTPUT ;
    USE SIGNAL ;
    PORT
      LAYER M5 ;
        RECT  29.904 0 29.928 0.084 ;
    END
  END o[296]
  PIN o[297]
    DIRECTION OUTPUT ;
    USE SIGNAL ;
    PORT
      LAYER M5 ;
        RECT  30 0 30.024 0.084 ;
    END
  END o[297]
  PIN o[298]
    DIRECTION OUTPUT ;
    USE SIGNAL ;
    PORT
      LAYER M5 ;
        RECT  30.096 0 30.12 0.084 ;
    END
  END o[298]
  PIN o[299]
    DIRECTION OUTPUT ;
    USE SIGNAL ;
    PORT
      LAYER M5 ;
        RECT  30.192 0 30.216 0.084 ;
    END
  END o[299]
  PIN o[29]
    DIRECTION OUTPUT ;
    USE SIGNAL ;
    PORT
      LAYER M5 ;
        RECT  15.792 0 15.816 0.084 ;
    END
  END o[29]
  PIN o[2]
    DIRECTION OUTPUT ;
    USE SIGNAL ;
    PORT
      LAYER M5 ;
        RECT  13.2 0 13.224 0.084 ;
    END
  END o[2]
  PIN o[300]
    DIRECTION OUTPUT ;
    USE SIGNAL ;
    PORT
      LAYER M5 ;
        RECT  30.288 0 30.312 0.084 ;
    END
  END o[300]
  PIN o[301]
    DIRECTION OUTPUT ;
    USE SIGNAL ;
    PORT
      LAYER M5 ;
        RECT  30.384 0 30.408 0.084 ;
    END
  END o[301]
  PIN o[302]
    DIRECTION OUTPUT ;
    USE SIGNAL ;
    PORT
      LAYER M5 ;
        RECT  30.48 0 30.504 0.084 ;
    END
  END o[302]
  PIN o[303]
    DIRECTION OUTPUT ;
    USE SIGNAL ;
    PORT
      LAYER M5 ;
        RECT  30.576 0 30.6 0.084 ;
    END
  END o[303]
  PIN o[30]
    DIRECTION OUTPUT ;
    USE SIGNAL ;
    PORT
      LAYER M5 ;
        RECT  15.888 0 15.912 0.084 ;
    END
  END o[30]
  PIN o[31]
    DIRECTION OUTPUT ;
    USE SIGNAL ;
    PORT
      LAYER M5 ;
        RECT  15.984 0 16.008 0.084 ;
    END
  END o[31]
  PIN o[32]
    DIRECTION OUTPUT ;
    USE SIGNAL ;
    PORT
      LAYER M5 ;
        RECT  3.792 0 3.816 0.084 ;
    END
  END o[32]
  PIN o[33]
    DIRECTION OUTPUT ;
    USE SIGNAL ;
    PORT
      LAYER M5 ;
        RECT  3.888 0 3.912 0.084 ;
    END
  END o[33]
  PIN o[34]
    DIRECTION OUTPUT ;
    USE SIGNAL ;
    PORT
      LAYER M5 ;
        RECT  3.984 0 4.008 0.084 ;
    END
  END o[34]
  PIN o[35]
    DIRECTION OUTPUT ;
    USE SIGNAL ;
    PORT
      LAYER M5 ;
        RECT  4.08 0 4.104 0.084 ;
    END
  END o[35]
  PIN o[36]
    DIRECTION OUTPUT ;
    USE SIGNAL ;
    PORT
      LAYER M5 ;
        RECT  4.176 0 4.2 0.084 ;
    END
  END o[36]
  PIN o[37]
    DIRECTION OUTPUT ;
    USE SIGNAL ;
    PORT
      LAYER M5 ;
        RECT  4.272 0 4.296 0.084 ;
    END
  END o[37]
  PIN o[38]
    DIRECTION OUTPUT ;
    USE SIGNAL ;
    PORT
      LAYER M5 ;
        RECT  4.368 0 4.392 0.084 ;
    END
  END o[38]
  PIN o[39]
    DIRECTION OUTPUT ;
    USE SIGNAL ;
    PORT
      LAYER M5 ;
        RECT  4.464 0 4.488 0.084 ;
    END
  END o[39]
  PIN o[3]
    DIRECTION OUTPUT ;
    USE SIGNAL ;
    PORT
      LAYER M5 ;
        RECT  13.296 0 13.32 0.084 ;
    END
  END o[3]
  PIN o[40]
    DIRECTION OUTPUT ;
    USE SIGNAL ;
    PORT
      LAYER M5 ;
        RECT  4.56 0 4.584 0.084 ;
    END
  END o[40]
  PIN o[41]
    DIRECTION OUTPUT ;
    USE SIGNAL ;
    PORT
      LAYER M5 ;
        RECT  4.656 0 4.68 0.084 ;
    END
  END o[41]
  PIN o[42]
    DIRECTION OUTPUT ;
    USE SIGNAL ;
    PORT
      LAYER M5 ;
        RECT  4.752 0 4.776 0.084 ;
    END
  END o[42]
  PIN o[43]
    DIRECTION OUTPUT ;
    USE SIGNAL ;
    PORT
      LAYER M5 ;
        RECT  4.848 0 4.872 0.084 ;
    END
  END o[43]
  PIN o[44]
    DIRECTION OUTPUT ;
    USE SIGNAL ;
    PORT
      LAYER M5 ;
        RECT  4.944 0 4.968 0.084 ;
    END
  END o[44]
  PIN o[45]
    DIRECTION OUTPUT ;
    USE SIGNAL ;
    PORT
      LAYER M5 ;
        RECT  5.04 0 5.064 0.084 ;
    END
  END o[45]
  PIN o[46]
    DIRECTION OUTPUT ;
    USE SIGNAL ;
    PORT
      LAYER M5 ;
        RECT  5.136 0 5.16 0.084 ;
    END
  END o[46]
  PIN o[47]
    DIRECTION OUTPUT ;
    USE SIGNAL ;
    PORT
      LAYER M5 ;
        RECT  5.232 0 5.256 0.084 ;
    END
  END o[47]
  PIN o[48]
    DIRECTION OUTPUT ;
    USE SIGNAL ;
    PORT
      LAYER M5 ;
        RECT  5.328 0 5.352 0.084 ;
    END
  END o[48]
  PIN o[49]
    DIRECTION OUTPUT ;
    USE SIGNAL ;
    PORT
      LAYER M5 ;
        RECT  5.424 0 5.448 0.084 ;
    END
  END o[49]
  PIN o[4]
    DIRECTION OUTPUT ;
    USE SIGNAL ;
    PORT
      LAYER M5 ;
        RECT  13.392 0 13.416 0.084 ;
    END
  END o[4]
  PIN o[50]
    DIRECTION OUTPUT ;
    USE SIGNAL ;
    PORT
      LAYER M5 ;
        RECT  5.52 0 5.544 0.084 ;
    END
  END o[50]
  PIN o[51]
    DIRECTION OUTPUT ;
    USE SIGNAL ;
    PORT
      LAYER M5 ;
        RECT  5.616 0 5.64 0.084 ;
    END
  END o[51]
  PIN o[52]
    DIRECTION OUTPUT ;
    USE SIGNAL ;
    PORT
      LAYER M5 ;
        RECT  5.712 0 5.736 0.084 ;
    END
  END o[52]
  PIN o[53]
    DIRECTION OUTPUT ;
    USE SIGNAL ;
    PORT
      LAYER M5 ;
        RECT  5.808 0 5.832 0.084 ;
    END
  END o[53]
  PIN o[54]
    DIRECTION OUTPUT ;
    USE SIGNAL ;
    PORT
      LAYER M5 ;
        RECT  5.904 0 5.928 0.084 ;
    END
  END o[54]
  PIN o[55]
    DIRECTION OUTPUT ;
    USE SIGNAL ;
    PORT
      LAYER M5 ;
        RECT  6 0 6.024 0.084 ;
    END
  END o[55]
  PIN o[56]
    DIRECTION OUTPUT ;
    USE SIGNAL ;
    PORT
      LAYER M5 ;
        RECT  6.096 0 6.12 0.084 ;
    END
  END o[56]
  PIN o[57]
    DIRECTION OUTPUT ;
    USE SIGNAL ;
    PORT
      LAYER M5 ;
        RECT  6.192 0 6.216 0.084 ;
    END
  END o[57]
  PIN o[58]
    DIRECTION OUTPUT ;
    USE SIGNAL ;
    PORT
      LAYER M5 ;
        RECT  6.288 0 6.312 0.084 ;
    END
  END o[58]
  PIN o[59]
    DIRECTION OUTPUT ;
    USE SIGNAL ;
    PORT
      LAYER M5 ;
        RECT  6.384 0 6.408 0.084 ;
    END
  END o[59]
  PIN o[5]
    DIRECTION OUTPUT ;
    USE SIGNAL ;
    PORT
      LAYER M5 ;
        RECT  13.488 0 13.512 0.084 ;
    END
  END o[5]
  PIN o[60]
    DIRECTION OUTPUT ;
    USE SIGNAL ;
    PORT
      LAYER M5 ;
        RECT  6.48 0 6.504 0.084 ;
    END
  END o[60]
  PIN o[61]
    DIRECTION OUTPUT ;
    USE SIGNAL ;
    PORT
      LAYER M5 ;
        RECT  6.576 0 6.6 0.084 ;
    END
  END o[61]
  PIN o[62]
    DIRECTION OUTPUT ;
    USE SIGNAL ;
    PORT
      LAYER M5 ;
        RECT  6.672 0 6.696 0.084 ;
    END
  END o[62]
  PIN o[63]
    DIRECTION OUTPUT ;
    USE SIGNAL ;
    PORT
      LAYER M5 ;
        RECT  6.768 0 6.792 0.084 ;
    END
  END o[63]
  PIN o[64]
    DIRECTION OUTPUT ;
    USE SIGNAL ;
    PORT
      LAYER M5 ;
        RECT  0.72 0 0.744 0.084 ;
    END
  END o[64]
  PIN o[65]
    DIRECTION OUTPUT ;
    USE SIGNAL ;
    PORT
      LAYER M5 ;
        RECT  0.816 0 0.84 0.084 ;
    END
  END o[65]
  PIN o[66]
    DIRECTION OUTPUT ;
    USE SIGNAL ;
    PORT
      LAYER M5 ;
        RECT  0.912 0 0.936 0.084 ;
    END
  END o[66]
  PIN o[67]
    DIRECTION OUTPUT ;
    USE SIGNAL ;
    PORT
      LAYER M5 ;
        RECT  1.008 0 1.032 0.084 ;
    END
  END o[67]
  PIN o[68]
    DIRECTION OUTPUT ;
    USE SIGNAL ;
    PORT
      LAYER M5 ;
        RECT  1.104 0 1.128 0.084 ;
    END
  END o[68]
  PIN o[69]
    DIRECTION OUTPUT ;
    USE SIGNAL ;
    PORT
      LAYER M5 ;
        RECT  1.2 0 1.224 0.084 ;
    END
  END o[69]
  PIN o[6]
    DIRECTION OUTPUT ;
    USE SIGNAL ;
    PORT
      LAYER M5 ;
        RECT  13.584 0 13.608 0.084 ;
    END
  END o[6]
  PIN o[70]
    DIRECTION OUTPUT ;
    USE SIGNAL ;
    PORT
      LAYER M5 ;
        RECT  1.296 0 1.32 0.084 ;
    END
  END o[70]
  PIN o[71]
    DIRECTION OUTPUT ;
    USE SIGNAL ;
    PORT
      LAYER M5 ;
        RECT  1.392 0 1.416 0.084 ;
    END
  END o[71]
  PIN o[72]
    DIRECTION OUTPUT ;
    USE SIGNAL ;
    PORT
      LAYER M5 ;
        RECT  1.488 0 1.512 0.084 ;
    END
  END o[72]
  PIN o[73]
    DIRECTION OUTPUT ;
    USE SIGNAL ;
    PORT
      LAYER M5 ;
        RECT  1.584 0 1.608 0.084 ;
    END
  END o[73]
  PIN o[74]
    DIRECTION OUTPUT ;
    USE SIGNAL ;
    PORT
      LAYER M5 ;
        RECT  1.68 0 1.704 0.084 ;
    END
  END o[74]
  PIN o[75]
    DIRECTION OUTPUT ;
    USE SIGNAL ;
    PORT
      LAYER M5 ;
        RECT  1.776 0 1.8 0.084 ;
    END
  END o[75]
  PIN o[76]
    DIRECTION OUTPUT ;
    USE SIGNAL ;
    PORT
      LAYER M5 ;
        RECT  1.872 0 1.896 0.084 ;
    END
  END o[76]
  PIN o[77]
    DIRECTION OUTPUT ;
    USE SIGNAL ;
    PORT
      LAYER M5 ;
        RECT  1.968 0 1.992 0.084 ;
    END
  END o[77]
  PIN o[78]
    DIRECTION OUTPUT ;
    USE SIGNAL ;
    PORT
      LAYER M5 ;
        RECT  2.064 0 2.088 0.084 ;
    END
  END o[78]
  PIN o[79]
    DIRECTION OUTPUT ;
    USE SIGNAL ;
    PORT
      LAYER M5 ;
        RECT  2.16 0 2.184 0.084 ;
    END
  END o[79]
  PIN o[7]
    DIRECTION OUTPUT ;
    USE SIGNAL ;
    PORT
      LAYER M5 ;
        RECT  13.68 0 13.704 0.084 ;
    END
  END o[7]
  PIN o[80]
    DIRECTION OUTPUT ;
    USE SIGNAL ;
    PORT
      LAYER M5 ;
        RECT  2.256 0 2.28 0.084 ;
    END
  END o[80]
  PIN o[81]
    DIRECTION OUTPUT ;
    USE SIGNAL ;
    PORT
      LAYER M5 ;
        RECT  2.352 0 2.376 0.084 ;
    END
  END o[81]
  PIN o[82]
    DIRECTION OUTPUT ;
    USE SIGNAL ;
    PORT
      LAYER M5 ;
        RECT  2.448 0 2.472 0.084 ;
    END
  END o[82]
  PIN o[83]
    DIRECTION OUTPUT ;
    USE SIGNAL ;
    PORT
      LAYER M5 ;
        RECT  2.544 0 2.568 0.084 ;
    END
  END o[83]
  PIN o[84]
    DIRECTION OUTPUT ;
    USE SIGNAL ;
    PORT
      LAYER M5 ;
        RECT  2.64 0 2.664 0.084 ;
    END
  END o[84]
  PIN o[85]
    DIRECTION OUTPUT ;
    USE SIGNAL ;
    PORT
      LAYER M5 ;
        RECT  2.736 0 2.76 0.084 ;
    END
  END o[85]
  PIN o[86]
    DIRECTION OUTPUT ;
    USE SIGNAL ;
    PORT
      LAYER M5 ;
        RECT  2.832 0 2.856 0.084 ;
    END
  END o[86]
  PIN o[87]
    DIRECTION OUTPUT ;
    USE SIGNAL ;
    PORT
      LAYER M5 ;
        RECT  2.928 0 2.952 0.084 ;
    END
  END o[87]
  PIN o[88]
    DIRECTION OUTPUT ;
    USE SIGNAL ;
    PORT
      LAYER M5 ;
        RECT  3.024 0 3.048 0.084 ;
    END
  END o[88]
  PIN o[89]
    DIRECTION OUTPUT ;
    USE SIGNAL ;
    PORT
      LAYER M5 ;
        RECT  3.12 0 3.144 0.084 ;
    END
  END o[89]
  PIN o[8]
    DIRECTION OUTPUT ;
    USE SIGNAL ;
    PORT
      LAYER M5 ;
        RECT  13.776 0 13.8 0.084 ;
    END
  END o[8]
  PIN o[90]
    DIRECTION OUTPUT ;
    USE SIGNAL ;
    PORT
      LAYER M5 ;
        RECT  3.216 0 3.24 0.084 ;
    END
  END o[90]
  PIN o[91]
    DIRECTION OUTPUT ;
    USE SIGNAL ;
    PORT
      LAYER M5 ;
        RECT  3.312 0 3.336 0.084 ;
    END
  END o[91]
  PIN o[92]
    DIRECTION OUTPUT ;
    USE SIGNAL ;
    PORT
      LAYER M5 ;
        RECT  3.408 0 3.432 0.084 ;
    END
  END o[92]
  PIN o[93]
    DIRECTION OUTPUT ;
    USE SIGNAL ;
    PORT
      LAYER M5 ;
        RECT  3.504 0 3.528 0.084 ;
    END
  END o[93]
  PIN o[94]
    DIRECTION OUTPUT ;
    USE SIGNAL ;
    PORT
      LAYER M5 ;
        RECT  3.6 0 3.624 0.084 ;
    END
  END o[94]
  PIN o[95]
    DIRECTION OUTPUT ;
    USE SIGNAL ;
    PORT
      LAYER M5 ;
        RECT  3.696 0 3.72 0.084 ;
    END
  END o[95]
  PIN o[96]
    DIRECTION OUTPUT ;
    USE SIGNAL ;
    PORT
      LAYER M5 ;
        RECT  6.864 0 6.888 0.084 ;
    END
  END o[96]
  PIN o[97]
    DIRECTION OUTPUT ;
    USE SIGNAL ;
    PORT
      LAYER M5 ;
        RECT  6.96 0 6.984 0.084 ;
    END
  END o[97]
  PIN o[98]
    DIRECTION OUTPUT ;
    USE SIGNAL ;
    PORT
      LAYER M5 ;
        RECT  7.056 0 7.08 0.084 ;
    END
  END o[98]
  PIN o[99]
    DIRECTION OUTPUT ;
    USE SIGNAL ;
    PORT
      LAYER M5 ;
        RECT  7.152 0 7.176 0.084 ;
    END
  END o[99]
  PIN o[9]
    DIRECTION OUTPUT ;
    USE SIGNAL ;
    PORT
      LAYER M5 ;
        RECT  13.872 0 13.896 0.084 ;
    END
  END o[9]
  PIN rs
    DIRECTION INPUT ;
    USE SIGNAL ;
    PORT
      LAYER M4 ;
        RECT  0 15.888 0.084 15.912 ;
    END
  END rs
  PIN VDD
    DIRECTION INOUT ;
    USE POWER ;
    PORT
      LAYER M5 ;
        RECT  32.292 2.151 32.412 21.609 ;
        RECT  29.592 2.151 29.712 21.609 ;
        RECT  26.892 2.151 27.012 21.609 ;
        RECT  24.192 2.151 24.312 21.609 ;
        RECT  21.492 2.151 21.612 21.609 ;
        RECT  18.792 2.151 18.912 21.609 ;
        RECT  16.092 2.151 16.212 21.609 ;
        RECT  13.392 2.151 13.512 21.609 ;
        RECT  10.692 2.151 10.812 21.609 ;
        RECT  7.992 2.151 8.112 21.609 ;
        RECT  5.292 2.151 5.412 21.609 ;
        RECT  2.592 2.151 2.712 21.609 ;
    END
  END VDD
  PIN VSS
    DIRECTION INOUT ;
    USE GROUND ;
    PORT
      LAYER M5 ;
        RECT  32.1 2.137 32.22 21.623 ;
        RECT  29.4 2.137 29.52 21.623 ;
        RECT  26.7 2.137 26.82 21.623 ;
        RECT  24 2.137 24.12 21.623 ;
        RECT  21.3 2.137 21.42 21.623 ;
        RECT  18.6 2.137 18.72 21.623 ;
        RECT  15.9 2.137 16.02 21.623 ;
        RECT  13.2 2.137 13.32 21.623 ;
        RECT  10.5 2.137 10.62 21.623 ;
        RECT  7.8 2.137 7.92 21.623 ;
        RECT  5.1 2.137 5.22 21.623 ;
        RECT  2.4 2.137 2.52 21.623 ;
    END
  END VSS
  # OT_OBS_CLOSED layer=M5 d_um=1.536 added=77
  OBS
    LAYER RVTN ;
     RECT  2.16 2.16 32.4 2.295 ;
     RECT  2.16 2.565 32.4 2.835 ;
     RECT  2.16 3.105 32.4 3.375 ;
     RECT  2.16 3.645 32.4 3.915 ;
     RECT  2.16 4.185 32.4 4.455 ;
     RECT  2.16 4.725 32.4 4.995 ;
     RECT  2.16 5.265 32.4 5.535 ;
     RECT  2.16 5.805 32.4 6.075 ;
     RECT  2.16 6.345 32.4 6.615 ;
     RECT  2.16 6.885 32.4 7.155 ;
     RECT  2.16 7.425 32.4 7.695 ;
     RECT  2.16 7.965 32.4 8.235 ;
     RECT  2.16 8.505 32.4 8.775 ;
     RECT  2.16 9.045 32.4 9.315 ;
     RECT  2.16 9.585 32.4 9.855 ;
     RECT  2.16 10.125 32.4 10.395 ;
     RECT  2.16 10.665 32.4 10.935 ;
     RECT  2.16 11.205 32.4 11.475 ;
     RECT  2.16 11.745 32.4 12.015 ;
     RECT  2.16 12.285 32.4 12.555 ;
     RECT  2.16 12.825 32.4 13.095 ;
     RECT  2.16 13.365 32.4 13.635 ;
     RECT  2.16 13.905 32.4 14.175 ;
     RECT  2.16 14.445 32.4 14.715 ;
     RECT  2.16 14.985 32.4 15.255 ;
     RECT  2.16 15.525 32.4 15.795 ;
     RECT  2.16 16.065 32.4 16.335 ;
     RECT  2.16 16.605 32.4 16.875 ;
     RECT  2.16 17.145 32.4 17.415 ;
     RECT  2.16 17.685 32.4 17.955 ;
     RECT  2.16 18.225 32.4 18.495 ;
     RECT  2.16 18.765 32.4 19.035 ;
     RECT  2.16 19.305 32.4 19.575 ;
     RECT  2.16 19.845 32.4 20.115 ;
     RECT  2.16 20.385 32.4 20.655 ;
     RECT  2.16 20.925 32.4 21.195 ;
     RECT  2.16 21.465 32.4 21.6 ;
    LAYER RVTP ;
     RECT  2.16 2.295 32.4 2.565 ;
     RECT  2.16 2.835 32.4 3.105 ;
     RECT  2.16 3.375 32.4 3.645 ;
     RECT  2.16 3.915 32.4 4.185 ;
     RECT  2.16 4.455 32.4 4.725 ;
     RECT  2.16 4.995 32.4 5.265 ;
     RECT  2.16 5.535 32.4 5.805 ;
     RECT  2.16 6.075 32.4 6.345 ;
     RECT  2.16 6.615 32.4 6.885 ;
     RECT  2.16 7.155 32.4 7.425 ;
     RECT  2.16 7.695 32.4 7.965 ;
     RECT  2.16 8.235 32.4 8.505 ;
     RECT  2.16 8.775 32.4 9.045 ;
     RECT  2.16 9.315 32.4 9.585 ;
     RECT  2.16 9.855 32.4 10.125 ;
     RECT  2.16 10.395 32.4 10.665 ;
     RECT  2.16 10.935 32.4 11.205 ;
     RECT  2.16 11.475 32.4 11.745 ;
     RECT  2.16 12.015 32.4 12.285 ;
     RECT  2.16 12.555 32.4 12.825 ;
     RECT  2.16 13.095 32.4 13.365 ;
     RECT  2.16 13.635 32.4 13.905 ;
     RECT  2.16 14.175 32.4 14.445 ;
     RECT  2.16 14.715 32.4 14.985 ;
     RECT  2.16 15.255 32.4 15.525 ;
     RECT  2.16 15.795 32.4 16.065 ;
     RECT  2.16 16.335 32.4 16.605 ;
     RECT  2.16 16.875 32.4 17.145 ;
     RECT  2.16 17.415 32.4 17.685 ;
     RECT  2.16 17.955 32.4 18.225 ;
     RECT  2.16 18.495 32.4 18.765 ;
     RECT  2.16 19.035 32.4 19.305 ;
     RECT  2.16 19.575 32.4 19.845 ;
     RECT  2.16 20.115 32.4 20.385 ;
     RECT  2.16 20.655 32.4 20.925 ;
     RECT  2.16 21.195 32.4 21.465 ;
    LAYER M1 ;
     RECT  2.16 2.151 32.4 21.609 ;
    LAYER M2 ;
     RECT  1.723 4.194 1.759 4.212 ;
     RECT  0.931 3.186 1.795 3.204 ;
     RECT  1.759 4.194 1.795 4.824 ;
     RECT  1.111 2.106 1.867 2.124 ;
     RECT  1.867 1.998 1.903 2.124 ;
     RECT  1.795 3.15 1.903 3.204 ;
     RECT  1.867 6.318 1.903 6.336 ;
     RECT  1.939 9.396 2.047 9.414 ;
     RECT  1.795 10.296 2.047 10.314 ;
     RECT  2.047 9.396 2.083 10.314 ;
     RECT  1.795 4.122 2.119 4.824 ;
     RECT  2.083 8.856 2.155 10.314 ;
     RECT  1.903 1.998 2.16 3.204 ;
     RECT  2.119 4.122 2.16 5.094 ;
     RECT  1.903 6.012 2.16 6.336 ;
     RECT  2.011 7.362 2.16 7.38 ;
     RECT  2.155 8.856 2.16 10.422 ;
     RECT  2.16 1.998 3.011 21.609 ;
     RECT  3.011 2.151 5.611 21.609 ;
     RECT  5.611 2.106 5.711 21.609 ;
     RECT  5.711 2.151 9.031 21.609 ;
     RECT  9.031 2.106 10.067 21.609 ;
     RECT  10.067 2.151 12.163 21.609 ;
     RECT  12.163 2.034 13.631 21.609 ;
     RECT  13.631 2.151 14.683 21.609 ;
     RECT  15.007 1.152 15.107 1.17 ;
     RECT  14.683 2.106 15.179 21.609 ;
     RECT  15.179 2.151 21.019 21.609 ;
     RECT  21.019 2.106 21.299 21.609 ;
     RECT  21.299 2.151 22.891 21.609 ;
     RECT  22.891 2.106 24.683 21.609 ;
     RECT  24.683 2.151 26.743 21.609 ;
     RECT  26.743 2.07 27.023 21.609 ;
     RECT  27.023 2.151 28.579 21.609 ;
     RECT  28.579 2.106 31.055 21.609 ;
     RECT  31.055 2.151 32.4 21.609 ;
     RECT  32.4 2.421 32.412 21.339 ;
     RECT  32.412 9.558 32.459 9.576 ;
     RECT  32.412 10.908 32.459 10.926 ;
     RECT  32.412 11.826 32.459 11.844 ;
     RECT  32.412 15.3 32.459 16.092 ;
     RECT  32.412 20.286 32.459 21.114 ;
     RECT  32.459 15.3 32.495 15.318 ;
     RECT  32.459 20.286 32.495 20.988 ;
     RECT  32.412 17.658 32.531 19.368 ;
     RECT  32.531 17.658 32.567 19.026 ;
     RECT  32.567 17.928 33.035 19.026 ;
     RECT  32.495 20.7 33.107 20.988 ;
     RECT  33.035 17.928 33.143 18.018 ;
     RECT  33.143 17.928 33.215 17.946 ;
     RECT  32.459 16.074 33.503 16.092 ;
     RECT  33.035 19.008 33.755 19.026 ;
    LAYER M3 ;
     RECT  2.808 0.091 3.834 0.139 ;
     RECT  14.184 0.091 14.202 0.139 ;
     RECT  23.04 0.091 23.058 0.139 ;
     RECT  7.416 0.091 9.522 0.221 ;
     RECT  7.416 0.221 7.434 0.317 ;
     RECT  5.544 0.091 5.742 0.365 ;
     RECT  23.04 0.139 23.166 0.475 ;
     RECT  24.156 0.091 24.174 0.475 ;
     RECT  15.768 0.091 16.074 0.523 ;
     RECT  2.736 0.139 3.834 0.571 ;
     RECT  23.04 0.475 24.174 0.571 ;
     RECT  25.38 0.091 25.398 0.571 ;
     RECT  26.496 0.091 26.874 0.571 ;
     RECT  28.008 0.091 29.754 0.571 ;
     RECT  2.304 0.571 3.834 1.099 ;
     RECT  11.124 0.571 11.142 1.099 ;
     RECT  12.204 0.571 13.41 1.099 ;
     RECT  20.448 0.571 20.466 1.099 ;
     RECT  21.24 1.051 21.258 1.099 ;
     RECT  11.124 1.099 13.41 1.147 ;
     RECT  14.184 0.139 14.274 1.147 ;
     RECT  15.012 0.523 15.03 1.147 ;
     RECT  15.768 0.523 16.542 1.147 ;
     RECT  20.448 1.099 21.258 1.147 ;
     RECT  22.572 0.571 24.174 1.147 ;
     RECT  2.088 1.099 3.834 1.723 ;
     RECT  4.644 0.571 4.662 1.723 ;
     RECT  5.976 0.571 5.994 1.723 ;
     RECT  7.092 1.147 7.11 1.723 ;
     RECT  8.208 0.221 9.522 1.723 ;
     RECT  11.124 1.147 14.274 1.723 ;
     RECT  15.012 1.147 16.542 1.723 ;
     RECT  17.28 1.147 17.514 1.723 ;
     RECT  18.972 0.091 18.99 1.723 ;
     RECT  20.448 1.147 24.174 1.723 ;
     RECT  25.236 0.571 25.398 1.723 ;
     RECT  26.496 0.571 29.754 1.723 ;
     RECT  5.508 1.723 30.762 1.867 ;
     RECT  1.116 1.723 4.662 2.129 ;
     RECT  1.8 2.129 4.662 2.143 ;
     RECT  5.508 1.867 31.374 2.143 ;
     RECT  32.115 2.143 32.205 2.413 ;
     RECT  1.8 2.143 31.374 2.641 ;
     RECT  32.115 2.413 32.397 2.641 ;
     RECT  1.8 2.641 32.397 2.875 ;
     RECT  0.936 2.923 0.954 3.209 ;
     RECT  1.764 2.875 32.397 3.979 ;
     RECT  1.728 3.979 32.397 4.217 ;
     RECT  1.764 4.217 32.397 4.829 ;
     RECT  1.8 4.829 32.397 9.553 ;
     RECT  1.8 9.553 32.454 10.319 ;
     RECT  2.16 10.319 32.454 10.427 ;
     RECT  2.304 10.427 32.454 10.931 ;
     RECT  2.304 10.931 32.397 11.669 ;
     RECT  2.415 11.669 32.397 11.821 ;
     RECT  2.415 11.821 32.454 15.295 ;
     RECT  2.412 15.295 32.49 15.565 ;
     RECT  2.376 15.565 32.49 15.835 ;
     RECT  2.304 15.835 32.49 17.149 ;
     RECT  2.232 17.149 32.49 17.653 ;
     RECT  2.232 17.653 32.562 17.923 ;
     RECT  33.48 16.069 33.498 17.923 ;
     RECT  2.232 17.923 33.498 19.003 ;
     RECT  2.232 19.003 33.75 19.571 ;
     RECT  2.304 19.571 33.75 21.101 ;
     RECT  2.304 21.101 33.498 21.347 ;
     RECT  2.304 21.347 32.205 21.389 ;
     RECT  14.976 21.389 32.205 21.461 ;
     RECT  14.976 21.461 30.87 21.569 ;
     RECT  14.976 21.569 30.618 21.581 ;
     RECT  32.115 21.461 32.205 21.617 ;
     RECT  2.34 21.389 14.238 21.677 ;
     RECT  14.976 21.581 30.402 21.677 ;
     RECT  4.5 21.677 8.154 21.725 ;
     RECT  22.716 21.677 24.534 21.725 ;
     RECT  25.524 21.677 25.65 21.725 ;
     RECT  2.34 21.677 3.69 21.773 ;
     RECT  4.5 21.725 7.974 21.773 ;
     RECT  9.072 21.677 11.106 21.773 ;
     RECT  12.024 21.677 14.238 21.773 ;
     RECT  26.604 21.677 29.574 21.773 ;
     RECT  26.604 21.773 29.394 21.821 ;
     RECT  2.376 21.773 3.69 21.869 ;
     RECT  4.5 21.773 7.218 21.869 ;
     RECT  13.608 21.773 14.238 22.205 ;
     RECT  2.556 21.869 3.69 22.253 ;
     RECT  5.58 21.869 7.218 22.253 ;
     RECT  14.976 21.677 21.942 22.253 ;
     RECT  22.752 21.725 24.534 22.253 ;
     RECT  26.604 21.821 29.07 22.253 ;
     RECT  5.58 22.253 6.534 22.301 ;
     RECT  21.672 22.253 21.834 22.301 ;
     RECT  26.604 22.253 27.738 22.445 ;
     RECT  6.516 22.301 6.534 22.781 ;
     RECT  13.644 22.205 14.238 22.781 ;
     RECT  14.976 22.253 20.466 22.781 ;
     RECT  14.184 22.781 14.238 22.792 ;
     RECT  2.556 22.253 2.862 22.829 ;
     RECT  5.58 22.301 5.67 22.829 ;
     RECT  11.088 21.773 11.106 22.829 ;
     RECT  14.976 22.781 17.01 22.829 ;
     RECT  18.18 22.781 20.466 22.829 ;
     RECT  22.752 22.253 23.994 22.829 ;
     RECT  26.856 22.445 27.738 22.829 ;
     RECT  2.808 22.829 2.862 22.877 ;
     RECT  4.5 21.869 4.518 22.877 ;
     RECT  5.58 22.829 5.598 22.877 ;
     RECT  9.072 21.773 10.134 22.877 ;
     RECT  14.184 22.792 14.202 22.877 ;
     RECT  16.236 22.829 16.254 22.877 ;
     RECT  23.4 22.829 23.994 22.877 ;
     RECT  27.72 22.829 27.738 22.877 ;
     RECT  3.672 22.253 3.69 22.925 ;
     RECT  12.024 21.773 12.474 23.597 ;
     RECT  2.844 22.877 2.862 23.645 ;
     RECT  9.54 22.877 9.558 23.645 ;
     RECT  12.456 23.597 12.474 23.645 ;
     RECT  18.36 22.829 18.378 23.645 ;
     RECT  21.816 22.301 21.834 23.645 ;
     RECT  23.976 22.877 23.994 23.645 ;
     RECT  25.524 21.725 25.542 23.645 ;
     RECT  26.856 22.829 26.874 23.645 ;
     RECT  33.012 21.347 33.498 23.645 ;
    LAYER M4 ;
     RECT  0.06 15.792 0.133 15.912 ;
     RECT  0.133 15.792 0.179 16.344 ;
     RECT  0.709 2.256 0.805 2.28 ;
     RECT  0.805 2.256 0.881 2.904 ;
     RECT  0.881 2.256 0.965 2.952 ;
     RECT  0.965 2.256 1.061 2.904 ;
     RECT  1.285 7.968 1.381 7.992 ;
     RECT  1.189 0.576 1.477 0.6 ;
     RECT  1.573 3.984 1.669 4.008 ;
     RECT  0.997 10.32 1.861 10.344 ;
     RECT  1.061 1.728 2.005 2.904 ;
     RECT  1.669 3.984 2.005 4.68 ;
     RECT  1.477 0.576 2.077 0.648 ;
     RECT  2.005 1.728 2.077 4.68 ;
     RECT  2.077 0.576 2.101 4.68 ;
     RECT  1.381 7.44 2.197 7.992 ;
     RECT  2.197 7.44 2.293 8.04 ;
     RECT  2.329 21.744 2.365 21.768 ;
     RECT  2.101 0.144 2.408 4.68 ;
     RECT  2.293 6.336 2.408 8.04 ;
     RECT  2.053 9.264 2.408 9.288 ;
     RECT  1.861 10.32 2.408 10.392 ;
     RECT  2.245 13.104 2.408 13.128 ;
     RECT  0.179 15.888 2.408 16.344 ;
     RECT  2.293 17.664 2.408 17.688 ;
     RECT  2.365 20.112 2.408 20.136 ;
     RECT  2.365 21.744 2.408 21.864 ;
     RECT  2.408 0.144 2.483 21.864 ;
     RECT  2.483 1.728 2.545 21.864 ;
     RECT  2.533 23.376 2.545 23.4 ;
     RECT  2.545 1.728 2.629 23.4 ;
     RECT  2.629 1.728 2.704 23.496 ;
     RECT  2.483 0.144 2.765 0.648 ;
     RECT  2.765 0.144 2.78 0.6 ;
     RECT  2.704 21.12 2.789 23.496 ;
     RECT  2.704 1.728 2.819 6.36 ;
     RECT  2.704 15.936 2.819 19.08 ;
     RECT  2.789 21.12 2.905 23.64 ;
     RECT  2.704 9.12 2.945 10.344 ;
     RECT  2.704 14.784 2.945 14.904 ;
     RECT  2.704 7.44 3.305 8.04 ;
     RECT  2.819 18.432 3.449 19.08 ;
     RECT  2.704 13.104 3.521 13.128 ;
     RECT  2.905 21.12 3.635 22.92 ;
     RECT  2.945 9.12 3.683 10.296 ;
     RECT  2.945 14.832 3.697 14.904 ;
     RECT  2.819 15.936 3.697 17.112 ;
     RECT  2.78 0.096 3.845 0.6 ;
     RECT  3.697 14.832 3.941 17.112 ;
     RECT  3.449 18.432 3.941 18.744 ;
     RECT  2.819 1.728 3.949 6.312 ;
     RECT  3.941 14.832 3.949 18.744 ;
     RECT  3.683 9.696 4.025 10.296 ;
     RECT  3.635 22.8 4.211 22.92 ;
     RECT  3.949 14.496 4.309 18.744 ;
     RECT  3.949 1.728 4.381 6.888 ;
     RECT  3.305 7.968 4.381 8.04 ;
     RECT  2.704 20.112 4.453 20.136 ;
     RECT  3.635 21.12 4.453 21.672 ;
     RECT  4.211 22.8 4.499 22.872 ;
     RECT  4.499 22.848 4.595 22.872 ;
     RECT  4.165 11.424 4.661 11.448 ;
     RECT  3.845 0.576 4.673 0.6 ;
     RECT  4.661 11.424 4.885 12.024 ;
     RECT  4.453 20.112 4.993 21.672 ;
     RECT  4.381 1.728 5.108 8.04 ;
     RECT  4.885 11.424 5.108 12.552 ;
     RECT  4.309 14.256 5.108 18.744 ;
     RECT  4.993 20.112 5.108 21.864 ;
     RECT  5.108 1.728 5.404 21.864 ;
     RECT  4.885 0.144 5.489 0.504 ;
     RECT  5.404 14.256 5.605 21.864 ;
     RECT  5.569 22.848 5.605 22.872 ;
     RECT  5.489 0.096 5.701 0.504 ;
     RECT  5.404 1.728 5.795 6.888 ;
     RECT  5.701 0.096 5.843 0.6 ;
     RECT  5.404 13.104 5.869 13.128 ;
     RECT  5.843 0.24 5.891 0.6 ;
     RECT  5.605 14.256 5.933 22.872 ;
     RECT  5.404 10.272 5.941 10.824 ;
     RECT  5.891 0.288 5.987 0.6 ;
     RECT  5.987 0.576 6.005 0.6 ;
     RECT  5.795 5.136 6.041 6.888 ;
     RECT  5.404 7.968 6.157 7.992 ;
     RECT  5.933 14.256 6.293 20.136 ;
     RECT  5.933 21.12 6.325 22.872 ;
     RECT  6.041 5.136 6.329 6.312 ;
     RECT  5.941 10.272 6.409 10.296 ;
     RECT  5.795 1.728 6.853 3.864 ;
     RECT  6.325 21.12 6.995 23.592 ;
     RECT  6.853 1.152 7.121 3.864 ;
     RECT  6.293 14.256 7.189 19.656 ;
     RECT  6.329 5.136 7.292 5.736 ;
     RECT  7.189 13.68 7.297 19.656 ;
     RECT  7.333 0.096 7.381 0.12 ;
     RECT  7.121 1.728 7.429 3.864 ;
     RECT  7.292 4.848 7.429 5.736 ;
     RECT  7.429 1.728 7.477 5.736 ;
     RECT  6.995 21.12 7.571 22.248 ;
     RECT  7.297 13.68 7.693 19.992 ;
     RECT  7.571 21.12 7.693 21.768 ;
     RECT  7.381 0.096 7.756 0.312 ;
     RECT  7.477 1.728 7.808 5.784 ;
     RECT  7.693 13.68 7.808 21.768 ;
     RECT  7.808 1.728 7.996 21.768 ;
     RECT  7.996 1.728 8.104 21.72 ;
     RECT  8.104 13.488 8.165 21.72 ;
     RECT  8.104 1.728 8.197 3.864 ;
     RECT  8.104 5.52 8.201 6.6 ;
     RECT  8.201 5.712 8.345 6.6 ;
     RECT  8.345 6.576 8.417 6.6 ;
     RECT  8.104 9.12 8.425 9.72 ;
     RECT  8.197 1.152 8.453 3.864 ;
     RECT  8.165 13.488 8.597 21.672 ;
     RECT  8.104 10.848 8.777 12.024 ;
     RECT  8.597 13.68 8.813 21.672 ;
     RECT  8.777 10.848 8.857 10.92 ;
     RECT  7.756 0.096 8.869 0.168 ;
     RECT  8.813 18 8.915 21.672 ;
     RECT  8.915 18 8.921 19.848 ;
     RECT  8.869 0.096 9.029 0.6 ;
     RECT  8.425 9.696 9.037 9.72 ;
     RECT  6.995 23.568 9.061 23.592 ;
     RECT  8.915 21.12 9.065 21.672 ;
     RECT  9.061 22.848 9.097 23.592 ;
     RECT  8.453 1.728 9.109 3.864 ;
     RECT  8.857 10.848 9.155 10.872 ;
     RECT  8.813 13.68 9.245 16.536 ;
     RECT  9.097 22.752 9.299 23.592 ;
     RECT  9.313 5.088 9.397 5.112 ;
     RECT  9.299 22.8 9.529 23.592 ;
     RECT  9.029 0.096 9.533 0.12 ;
     RECT  9.637 6.288 9.829 6.312 ;
     RECT  9.529 22.8 9.875 23.64 ;
     RECT  9.349 12.576 10.069 12.6 ;
     RECT  9.065 21.168 10.141 21.672 ;
     RECT  9.109 1.728 10.172 1.848 ;
     RECT  9.109 2.832 10.172 3.864 ;
     RECT  8.921 18.144 10.249 19.848 ;
     RECT  10.172 1.728 10.277 3.864 ;
     RECT  9.245 13.968 10.277 16.536 ;
     RECT  10.249 17.712 10.277 19.848 ;
     RECT  10.141 21.12 10.364 21.672 ;
     RECT  10.277 1.728 10.508 4.008 ;
     RECT  9.829 5.28 10.508 6.312 ;
     RECT  9.485 8.544 10.508 8.568 ;
     RECT  9.877 10.896 10.508 10.968 ;
     RECT  10.069 12.528 10.508 12.6 ;
     RECT  10.277 13.968 10.508 19.848 ;
     RECT  10.364 21.12 10.508 21.72 ;
     RECT  10.261 0.144 10.547 0.216 ;
     RECT  9.875 22.8 10.643 23.544 ;
     RECT  10.508 1.728 10.748 21.72 ;
     RECT  10.748 1.728 10.804 21.768 ;
     RECT  10.804 21.12 10.835 21.768 ;
     RECT  10.547 0.192 11.069 0.216 ;
     RECT  10.804 10.848 11.197 11.448 ;
     RECT  10.804 1.728 11.315 3.48 ;
     RECT  11.315 1.728 11.405 1.8 ;
     RECT  11.069 0.192 11.42 0.6 ;
     RECT  10.804 4.464 11.459 5.784 ;
     RECT  10.643 22.8 11.507 22.824 ;
     RECT  11.42 0.192 11.653 1.128 ;
     RECT  11.197 10.848 11.873 10.968 ;
     RECT  11.653 0.144 11.891 1.128 ;
     RECT  11.315 2.784 11.891 3.48 ;
     RECT  11.833 9.696 11.917 9.72 ;
     RECT  10.804 18.72 11.981 20.088 ;
     RECT  10.804 13.968 12.013 17.736 ;
     RECT  11.981 18.72 12.013 19.416 ;
     RECT  12.013 13.968 12.097 19.416 ;
     RECT  11.459 4.512 12.113 5.784 ;
     RECT  12.097 13.968 12.181 19.272 ;
     RECT  12.113 4.512 12.197 5.88 ;
     RECT  11.605 23.568 12.445 23.592 ;
     RECT  11.891 2.832 12.553 3.48 ;
     RECT  12.197 4.512 12.553 5.784 ;
     RECT  12.445 23.568 12.563 23.64 ;
     RECT  12.409 12.528 12.625 12.552 ;
     RECT  12.563 23.568 12.659 23.592 ;
     RECT  10.835 21.12 12.769 21.672 ;
     RECT  12.769 21.072 13.129 21.672 ;
     RECT  12.421 1.728 13.165 1.752 ;
     RECT  12.553 2.832 13.165 5.784 ;
     RECT  13.165 1.728 13.208 5.784 ;
     RECT  11.873 10.848 13.208 10.872 ;
     RECT  12.625 12 13.208 12.552 ;
     RECT  12.181 13.584 13.208 19.272 ;
     RECT  13.129 21.072 13.208 21.768 ;
     RECT  11.891 0.144 13.429 0.6 ;
     RECT  13.208 1.728 13.429 21.768 ;
     RECT  13.429 0.144 13.504 21.768 ;
     RECT  13.504 17.616 13.565 19.992 ;
     RECT  13.504 21.12 13.597 21.768 ;
     RECT  13.381 22.752 13.597 22.776 ;
     RECT  13.504 0.144 13.619 5.064 ;
     RECT  13.504 14.64 13.634 16.584 ;
     RECT  13.504 6.24 13.66 6.312 ;
     RECT  13.619 1.152 13.673 5.064 ;
     RECT  13.673 5.04 13.715 5.064 ;
     RECT  13.597 21.12 13.933 22.776 ;
     RECT  13.673 1.2 13.961 4.008 ;
     RECT  13.933 22.176 14.003 22.776 ;
     RECT  13.619 0.144 14.129 0.168 ;
     RECT  14.003 22.752 14.173 22.776 ;
     RECT  14.129 0.096 14.213 0.168 ;
     RECT  13.66 6.288 14.213 6.312 ;
     RECT  14.213 0.144 14.329 0.168 ;
     RECT  14.173 22.752 14.387 22.872 ;
     RECT  13.634 14.64 14.429 16.536 ;
     RECT  13.565 17.664 14.641 19.992 ;
     RECT  14.429 14.64 14.677 14.664 ;
     RECT  13.933 21.12 14.681 21.192 ;
     RECT  14.677 13.68 14.761 14.664 ;
     RECT  14.429 15.84 14.821 16.536 ;
     RECT  14.641 17.664 14.821 20.04 ;
     RECT  14.681 21.168 14.825 21.192 ;
     RECT  14.725 5.136 15.073 5.16 ;
     RECT  14.972 0.528 15.397 0.552 ;
     RECT  15.397 0.096 15.493 0.552 ;
     RECT  15.361 21.552 15.757 21.672 ;
     RECT  14.387 22.752 15.757 22.824 ;
     RECT  15.757 21.552 15.793 22.824 ;
     RECT  13.961 1.728 15.908 4.008 ;
     RECT  15.073 5.136 15.908 5.736 ;
     RECT  15.397 10.848 15.908 10.872 ;
     RECT  15.001 12.528 15.908 12.552 ;
     RECT  14.761 14.64 15.908 14.664 ;
     RECT  14.821 15.84 15.908 20.04 ;
     RECT  15.793 21.408 15.908 22.824 ;
     RECT  15.493 0.096 16.069 0.6 ;
     RECT  15.908 1.728 16.069 22.824 ;
     RECT  16.069 0.096 16.085 22.824 ;
     RECT  16.085 0.144 16.165 22.824 ;
     RECT  16.165 0.144 16.204 23.592 ;
     RECT  16.204 21.12 16.355 23.592 ;
     RECT  16.204 0.144 16.373 6.84 ;
     RECT  16.204 13.68 16.517 19.272 ;
     RECT  16.517 13.68 16.553 18.792 ;
     RECT  16.373 5.712 16.589 6.84 ;
     RECT  16.373 0.144 16.595 4.584 ;
     RECT  16.355 21.12 16.691 22.872 ;
     RECT  16.553 13.68 16.769 17.16 ;
     RECT  16.204 10.848 16.921 10.872 ;
     RECT  16.595 0.144 17.027 0.168 ;
     RECT  16.589 6.816 17.075 6.84 ;
     RECT  16.769 15.408 17.093 17.112 ;
     RECT  16.691 21.12 17.171 22.824 ;
     RECT  16.769 13.68 17.273 14.232 ;
     RECT  16.553 18.144 17.309 18.792 ;
     RECT  17.093 16.032 17.489 17.112 ;
     RECT  16.589 5.712 17.557 5.736 ;
     RECT  17.516 19.392 17.557 19.56 ;
     RECT  16.595 1.152 17.585 4.584 ;
     RECT  17.557 5.712 17.585 6.072 ;
     RECT  17.171 21.12 17.747 22.776 ;
     RECT  17.747 22.752 17.843 22.776 ;
     RECT  17.701 13.2 17.917 13.656 ;
     RECT  17.585 1.152 18.083 6.072 ;
     RECT  18.133 15.024 18.205 15.048 ;
     RECT  17.489 16.032 18.205 17.064 ;
     RECT  18.169 22.8 18.325 22.824 ;
     RECT  18.325 22.8 18.349 23.544 ;
     RECT  17.557 19.392 18.385 20.088 ;
     RECT  17.309 18.144 18.421 18.168 ;
     RECT  18.349 22.8 18.433 23.64 ;
     RECT  18.083 1.728 18.469 6.072 ;
     RECT  18.421 18.144 18.469 18.264 ;
     RECT  18.385 19.296 18.469 20.088 ;
     RECT  18.469 1.728 18.608 6.312 ;
     RECT  17.917 13.104 18.608 13.656 ;
     RECT  18.205 15.024 18.608 17.064 ;
     RECT  18.469 18.144 18.608 20.088 ;
     RECT  17.747 21.12 18.608 21.672 ;
     RECT  18.421 0.144 18.611 0.168 ;
     RECT  18.433 22.8 18.611 23.448 ;
     RECT  18.611 22.8 18.707 23.352 ;
     RECT  18.608 1.728 18.716 21.672 ;
     RECT  18.716 1.728 18.904 21.72 ;
     RECT  18.917 0.096 19.001 0.12 ;
     RECT  18.904 18.72 19.069 21.72 ;
     RECT  18.707 22.8 19.069 22.824 ;
     RECT  18.904 6.288 19.253 6.312 ;
     RECT  19.069 18.72 19.433 22.824 ;
     RECT  19.433 20.496 19.955 22.824 ;
     RECT  19.433 18.72 19.957 19.416 ;
     RECT  18.904 14.832 19.973 17.16 ;
     RECT  19.973 15.84 20.003 17.16 ;
     RECT  19.957 18.24 20.045 19.416 ;
     RECT  19.955 22.752 20.051 22.824 ;
     RECT  18.904 10.272 20.185 10.296 ;
     RECT  18.904 8.544 20.245 8.568 ;
     RECT  18.904 1.728 20.291 3.864 ;
     RECT  20.003 15.984 20.437 17.16 ;
     RECT  20.045 18.24 20.437 18.888 ;
     RECT  20.197 0.576 20.753 0.6 ;
     RECT  20.291 1.728 20.753 2.952 ;
     RECT  20.051 22.8 20.819 22.824 ;
     RECT  18.904 5.136 20.869 5.16 ;
     RECT  20.185 10.272 20.917 10.344 ;
     RECT  20.869 5.136 21.061 5.208 ;
     RECT  19.955 20.496 21.085 21.672 ;
     RECT  20.753 0.576 21.109 2.952 ;
     RECT  21.061 5.136 21.109 5.352 ;
     RECT  20.437 15.984 21.109 18.888 ;
     RECT  20.293 14.688 21.121 14.712 ;
     RECT  21.085 6.72 21.157 6.744 ;
     RECT  21.109 0.144 21.299 2.952 ;
     RECT  21.299 1.152 21.308 2.952 ;
     RECT  20.876 3.936 21.308 3.96 ;
     RECT  21.109 5.136 21.308 5.496 ;
     RECT  21.157 6.72 21.308 7.464 ;
     RECT  20.245 8.544 21.308 8.616 ;
     RECT  20.917 10.272 21.308 10.92 ;
     RECT  18.904 13.632 21.308 13.656 ;
     RECT  21.121 14.688 21.308 14.952 ;
     RECT  21.109 15.984 21.308 18.984 ;
     RECT  21.085 20.496 21.308 22.296 ;
     RECT  21.299 0.144 21.587 0.168 ;
     RECT  21.308 1.152 21.604 22.296 ;
     RECT  21.604 4.512 21.665 5.784 ;
     RECT  21.604 14.688 21.701 22.296 ;
     RECT  21.701 14.688 21.731 22.248 ;
     RECT  21.731 14.688 21.82 16.536 ;
     RECT  21.253 23.616 21.845 23.64 ;
     RECT  21.604 1.152 21.989 3.528 ;
     RECT  21.731 17.52 22.025 22.248 ;
     RECT  22.025 18 22.259 22.248 ;
     RECT  22.259 18 22.277 21.72 ;
     RECT  21.989 1.728 22.313 3.528 ;
     RECT  21.604 13.056 22.597 13.656 ;
     RECT  21.82 14.688 22.637 14.712 ;
     RECT  21.604 7.968 22.669 7.992 ;
     RECT  22.313 2.784 22.673 3.528 ;
     RECT  21.604 10.896 22.709 10.92 ;
     RECT  22.501 0.576 22.789 0.6 ;
     RECT  21.82 15.984 22.813 16.536 ;
     RECT  22.277 18 22.817 18.264 ;
     RECT  22.669 7.248 22.931 7.992 ;
     RECT  22.789 0.144 22.981 0.6 ;
     RECT  22.981 0.096 23.069 0.6 ;
     RECT  22.597 12.816 23.209 13.656 ;
     RECT  22.813 15.312 23.245 16.536 ;
     RECT  21.665 4.512 23.269 5.736 ;
     RECT  22.931 7.248 23.269 7.272 ;
     RECT  22.741 22.8 23.345 22.824 ;
     RECT  22.277 19.392 23.372 21.72 ;
     RECT  23.345 22.8 23.372 22.872 ;
     RECT  23.372 22.704 23.459 22.872 ;
     RECT  23.459 22.8 23.507 22.872 ;
     RECT  23.069 0.144 23.557 0.6 ;
     RECT  23.245 15.312 23.605 17.736 ;
     RECT  23.209 12.816 23.677 13.896 ;
     RECT  23.605 15.216 23.677 17.736 ;
     RECT  23.372 18.768 23.821 21.72 ;
     RECT  23.557 0.144 23.897 0.648 ;
     RECT  22.313 1.728 23.921 1.8 ;
     RECT  22.673 2.784 23.921 3.432 ;
     RECT  23.921 23.52 24.005 23.64 ;
     RECT  23.921 1.728 24.008 3.432 ;
     RECT  23.269 4.512 24.008 7.272 ;
     RECT  21.604 9.696 24.008 9.72 ;
     RECT  23.852 10.848 24.008 10.872 ;
     RECT  23.677 12.816 24.008 17.736 ;
     RECT  23.821 18.768 24.008 21.768 ;
     RECT  23.897 0.144 24.101 0.168 ;
     RECT  24.101 0.096 24.185 0.168 ;
     RECT  24.008 1.728 24.304 21.768 ;
     RECT  24.304 18.72 24.505 21.768 ;
     RECT  24.005 23.52 24.515 23.592 ;
     RECT  24.304 2.832 24.653 6.312 ;
     RECT  24.505 18.72 24.659 22.248 ;
     RECT  24.659 18.72 24.689 21.672 ;
     RECT  24.689 19.2 24.797 21.672 ;
     RECT  24.304 12 24.869 17.64 ;
     RECT  24.185 0.144 25.093 0.168 ;
     RECT  24.797 20.304 25.121 21.672 ;
     RECT  25.121 20.544 25.139 21.672 ;
     RECT  25.093 0.144 25.189 0.6 ;
     RECT  25.189 0.096 25.265 0.6 ;
     RECT  24.304 7.44 25.273 7.464 ;
     RECT  24.304 1.728 25.297 1.8 ;
     RECT  25.333 9.696 25.381 9.72 ;
     RECT  24.515 23.568 25.513 23.592 ;
     RECT  25.297 1.68 25.523 1.8 ;
     RECT  25.513 23.568 25.619 23.64 ;
     RECT  25.139 21.12 25.621 21.672 ;
     RECT  24.869 12.528 25.625 17.64 ;
     RECT  25.625 16.992 25.657 17.64 ;
     RECT  25.657 16.992 25.697 17.688 ;
     RECT  25.619 23.616 25.715 23.64 ;
     RECT  25.523 1.728 25.765 1.8 ;
     RECT  24.653 2.832 25.765 5.736 ;
     RECT  25.381 9.696 25.861 10.344 ;
     RECT  25.765 1.728 25.957 5.736 ;
     RECT  25.697 17.088 25.981 17.688 ;
     RECT  25.861 9.696 26.053 10.392 ;
     RECT  25.981 17.088 26.161 18.12 ;
     RECT  24.797 19.2 26.161 19.224 ;
     RECT  25.957 1.728 26.245 5.784 ;
     RECT  26.053 9.696 26.437 10.872 ;
     RECT  25.621 21.12 26.588 21.72 ;
     RECT  26.588 21.12 26.593 21.768 ;
     RECT  25.625 12.528 26.701 16.008 ;
     RECT  26.161 17.088 26.701 19.224 ;
     RECT  26.245 1.728 26.708 6.312 ;
     RECT  26.437 9.696 26.708 10.92 ;
     RECT  26.701 12.528 26.708 19.224 ;
     RECT  26.593 21.12 26.708 22.44 ;
     RECT  26.581 23.568 26.77 23.592 ;
     RECT  25.265 0.096 26.885 0.12 ;
     RECT  26.77 23.568 26.885 23.64 ;
     RECT  26.708 1.728 26.917 22.44 ;
     RECT  26.917 1.152 27.004 22.872 ;
     RECT  27.004 1.152 27.013 3.96 ;
     RECT  27.004 13.68 27.137 14.232 ;
     RECT  27.004 7.92 27.155 7.944 ;
     RECT  27.004 15.552 27.155 19.08 ;
     RECT  27.004 5.088 27.181 5.256 ;
     RECT  27.013 0.144 27.347 3.96 ;
     RECT  27.004 20.688 27.347 22.872 ;
     RECT  27.004 6.288 27.353 6.312 ;
     RECT  27.347 20.688 27.353 21.72 ;
     RECT  27.181 5.088 27.389 5.16 ;
     RECT  27.347 0.144 27.461 3.528 ;
     RECT  27.461 0.144 27.569 0.6 ;
     RECT  27.461 1.728 27.641 3.528 ;
     RECT  27.641 1.728 27.683 3.432 ;
     RECT  27.137 13.68 27.997 14.088 ;
     RECT  27.004 9.792 28.105 9.816 ;
     RECT  27.347 22.8 28.117 22.872 ;
     RECT  27.155 15.552 28.177 17.688 ;
     RECT  27.155 18.768 28.177 19.08 ;
     RECT  28.117 22.8 28.211 23.592 ;
     RECT  27.389 5.088 28.261 5.112 ;
     RECT  27.997 13.152 28.288 14.088 ;
     RECT  28.211 23.568 28.307 23.592 ;
     RECT  28.261 4.56 28.357 5.112 ;
     RECT  27.353 21.12 28.393 21.72 ;
     RECT  28.177 15.552 28.573 19.08 ;
     RECT  28.288 13.152 28.681 14.136 ;
     RECT  28.681 13.104 28.709 14.136 ;
     RECT  28.573 15.264 28.789 19.08 ;
     RECT  27.953 0.096 28.837 0.12 ;
     RECT  28.753 7.392 28.861 7.416 ;
     RECT  28.709 13.104 28.861 14.28 ;
     RECT  28.837 0.096 28.981 0.168 ;
     RECT  28.981 0.096 29.081 0.216 ;
     RECT  28.861 13.056 29.113 14.28 ;
     RECT  28.789 15.264 29.113 19.8 ;
     RECT  27.683 1.728 29.185 3.384 ;
     RECT  28.357 4.56 29.185 5.736 ;
     RECT  28.393 21.12 29.267 22.248 ;
     RECT  29.185 1.728 29.408 5.736 ;
     RECT  28.861 7.392 29.408 7.992 ;
     RECT  28.105 9.792 29.408 10.728 ;
     RECT  29.113 13.056 29.408 20.136 ;
     RECT  29.267 21.12 29.408 21.816 ;
     RECT  29.408 1.728 29.651 21.816 ;
     RECT  29.651 1.728 29.704 21.672 ;
     RECT  29.081 0.096 29.765 0.12 ;
     RECT  29.704 18.192 29.765 18.264 ;
     RECT  29.765 18.24 29.939 18.264 ;
     RECT  29.701 23.568 29.987 23.592 ;
     RECT  29.704 14.784 30.053 17.064 ;
     RECT  29.704 1.728 30.083 3.048 ;
     RECT  29.704 19.344 30.133 20.136 ;
     RECT  29.704 9.792 30.161 11.4 ;
     RECT  30.083 1.728 30.227 2.28 ;
     RECT  30.227 1.728 30.305 2.184 ;
     RECT  29.704 21.12 30.413 21.672 ;
     RECT  30.133 19.392 30.493 20.136 ;
     RECT  30.413 21.12 30.611 21.624 ;
     RECT  30.611 21.12 30.629 21.576 ;
     RECT  29.704 7.968 30.673 7.992 ;
     RECT  30.305 1.728 30.773 1.896 ;
     RECT  30.161 10.704 30.803 11.4 ;
     RECT  30.812 9.072 30.899 9.096 ;
     RECT  30.803 10.848 30.947 11.4 ;
     RECT  30.493 19.44 31.057 20.136 ;
     RECT  30.629 21.12 31.057 21.192 ;
     RECT  29.704 13.056 31.165 13.08 ;
     RECT  30.053 15.456 31.165 17.064 ;
     RECT  31.129 14.208 31.345 14.232 ;
     RECT  31.165 15.456 31.345 17.16 ;
     RECT  30.773 1.872 31.385 1.896 ;
     RECT  31.057 19.44 31.849 21.192 ;
     RECT  31.909 23.52 31.957 23.544 ;
     RECT  30.947 11.04 32.108 11.4 ;
     RECT  31.165 13.056 32.108 13.224 ;
     RECT  31.345 14.208 32.108 17.16 ;
     RECT  31.849 18.816 32.108 21.192 ;
     RECT  32.108 2.148 32.212 21.612 ;
     RECT  32.212 2.418 32.404 21.342 ;
     RECT  31.957 23.52 32.435 23.64 ;
     RECT  32.404 18.768 32.572 18.984 ;
     RECT  32.404 19.968 33.203 21.144 ;
     RECT  33.203 20.784 33.299 21.144 ;
     RECT  33.299 20.976 33.395 21.144 ;
     RECT  32.435 23.616 33.509 23.64 ;
     RECT  33.395 21.072 33.587 21.144 ;
     RECT  32.572 18.96 33.683 18.984 ;
     RECT  33.587 21.072 33.805 21.096 ;
    LAYER M5 ;
     RECT  0.72 0.016 30.6 1.859 ;
     RECT  20.688 1.859 30.6 1.907 ;
     RECT  32.1 2.137 32.22 2.151 ;
     RECT  0.72 1.859 19.704 2.291 ;
     RECT  20.688 1.907 30.216 2.291 ;
     RECT  0.816 2.291 19.704 2.915 ;
     RECT  0.912 2.915 19.704 2.963 ;
     RECT  1.008 2.963 19.704 3.301 ;
     RECT  20.688 2.291 30.072 3.301 ;
     RECT  1.008 3.301 30.072 5.747 ;
     RECT  7.344 5.747 27.672 6.323 ;
     RECT  28.704 5.747 30.072 7.957 ;
     RECT  28.704 7.957 30.648 9.061 ;
     RECT  1.008 5.747 6.36 9.731 ;
     RECT  14.688 6.323 27.672 9.731 ;
     RECT  22.608 9.731 27.672 9.827 ;
     RECT  3.84 9.731 6.36 10.307 ;
     RECT  14.688 9.731 21.612 10.307 ;
     RECT  1.008 9.731 2.712 10.355 ;
     RECT  20.208 10.307 21.612 10.355 ;
     RECT  1.872 10.355 2.712 10.403 ;
     RECT  28.704 9.061 30.888 10.837 ;
     RECT  7.344 6.323 13.512 10.931 ;
     RECT  20.928 10.355 21.612 10.931 ;
     RECT  28.704 10.837 30.936 11.029 ;
     RECT  32.1 2.151 32.412 11.029 ;
     RECT  4.176 10.307 6.12 11.459 ;
     RECT  7.344 10.931 11.16 11.459 ;
     RECT  7.344 11.459 10.812 12.035 ;
     RECT  22.608 9.827 27.336 12.035 ;
     RECT  9.36 12.035 10.812 12.563 ;
     RECT  12.432 10.931 13.512 12.563 ;
     RECT  14.688 10.307 18.912 12.563 ;
     RECT  25.44 12.035 27.336 12.563 ;
     RECT  9.36 12.563 9.384 12.611 ;
     RECT  22.608 12.035 24.312 12.851 ;
     RECT  2.256 10.403 2.712 13.139 ;
     RECT  25.44 12.563 25.464 13.139 ;
     RECT  28.704 11.029 32.412 13.139 ;
     RECT  15.9 12.563 18.912 13.235 ;
     RECT  7.344 12.035 8.112 13.669 ;
     RECT  14.688 12.563 14.712 13.715 ;
     RECT  15.9 13.235 17.16 13.715 ;
     RECT  26.7 12.563 27.336 13.763 ;
     RECT  22.896 12.851 24.312 14.101 ;
     RECT  4.416 11.459 6.12 14.291 ;
     RECT  28.752 13.139 32.412 14.291 ;
     RECT  5.1 14.291 6.12 14.341 ;
     RECT  7.344 13.669 8.232 14.341 ;
     RECT  5.1 14.341 8.232 14.387 ;
     RECT  22.896 14.101 24.408 14.437 ;
     RECT  21.12 10.931 21.612 14.677 ;
     RECT  26.7 13.763 27.144 14.773 ;
     RECT  5.1 14.387 6.744 15.251 ;
     RECT  21.12 14.677 21.768 15.491 ;
     RECT  25.728 14.773 27.144 15.541 ;
     RECT  13.2 12.563 13.512 15.829 ;
     RECT  7.8 14.387 8.112 15.925 ;
     RECT  25.728 15.541 27.384 16.019 ;
     RECT  28.8 14.291 32.412 16.117 ;
     RECT  0.144 15.781 0.168 16.355 ;
     RECT  21.12 15.491 21.72 16.595 ;
     RECT  26.7 16.019 27.384 16.595 ;
     RECT  17.424 16.501 17.448 16.643 ;
     RECT  21.3 16.595 21.72 16.643 ;
     RECT  12.192 13.573 12.216 16.645 ;
     RECT  13.2 15.829 13.656 16.645 ;
     RECT  12.192 16.645 13.656 16.789 ;
     RECT  14.832 16.501 14.856 16.931 ;
     RECT  22.896 14.437 24.456 16.981 ;
     RECT  28.464 16.117 32.412 16.981 ;
     RECT  5.1 15.251 6.12 17.077 ;
     RECT  4.608 17.077 6.12 17.125 ;
     RECT  10.5 12.563 10.812 17.125 ;
     RECT  28.416 16.981 32.412 17.315 ;
     RECT  3.984 17.125 6.12 17.461 ;
     RECT  7.248 15.925 8.112 17.461 ;
     RECT  22.896 16.981 25.176 17.461 ;
     RECT  3.984 17.461 8.112 17.555 ;
     RECT  21.3 16.643 21.612 17.557 ;
     RECT  26.7 16.595 27.144 17.605 ;
     RECT  2.4 13.139 2.712 17.653 ;
     RECT  4.176 17.555 8.112 17.989 ;
     RECT  21.168 17.557 21.612 17.989 ;
     RECT  22.896 17.461 25.368 17.989 ;
     RECT  26.7 17.605 27.72 17.989 ;
     RECT  4.176 17.989 8.856 18.133 ;
     RECT  10.32 17.125 10.812 18.133 ;
     RECT  19.968 15.829 19.992 18.275 ;
     RECT  21.168 17.989 27.72 18.277 ;
     RECT  17.568 18.133 17.592 18.565 ;
     RECT  18.6 13.235 18.912 18.565 ;
     RECT  4.176 18.133 10.812 18.709 ;
     RECT  12.048 16.789 13.656 18.709 ;
     RECT  17.568 18.565 18.912 18.709 ;
     RECT  2.4 17.653 2.808 18.757 ;
     RECT  21.12 18.277 27.72 18.757 ;
     RECT  28.8 17.315 32.412 18.757 ;
     RECT  4.176 18.709 13.656 18.805 ;
     RECT  21.12 18.757 32.52 18.995 ;
     RECT  4.176 18.805 13.704 19.093 ;
     RECT  21.168 18.995 32.52 19.811 ;
     RECT  29.4 19.811 32.52 19.957 ;
     RECT  33.648 18.949 33.672 19.957 ;
     RECT  17.568 18.709 19.848 20.099 ;
     RECT  18.336 20.099 19.848 20.485 ;
     RECT  21.168 19.811 28.152 20.485 ;
     RECT  29.4 19.957 33.672 20.579 ;
     RECT  31.728 20.579 33.672 21.061 ;
     RECT  2.4 18.757 2.856 21.109 ;
     RECT  4.176 19.093 13.8 21.109 ;
     RECT  15.9 13.715 16.212 21.109 ;
     RECT  18.336 20.485 28.152 21.109 ;
     RECT  29.4 20.579 30.696 21.109 ;
     RECT  31.728 21.061 33.768 21.155 ;
     RECT  2.4 21.109 14.472 21.157 ;
     RECT  31.824 21.155 33.768 21.203 ;
     RECT  15.9 21.109 30.696 21.541 ;
     RECT  2.4 21.157 14.568 21.637 ;
     RECT  15.792 21.541 30.696 21.637 ;
     RECT  2.4 21.637 30.696 21.733 ;
     RECT  31.92 21.203 33.768 23.555 ;
     RECT  31.968 23.555 33.768 23.651 ;
     RECT  2.352 21.733 30.696 23.696 ;
     RECT  32.304 23.651 33.768 23.696 ;
     RECT  19.704 1.859 20.688 3.301 ;
     RECT  6.36 5.747 7.344 10.307 ;
     RECT  27.672 5.747 28.704 9.827 ;
     RECT  13.512 6.323 14.688 13.715 ;
     RECT  30.648 7.957 32.1 9.061 ;
     RECT  30.888 9.061 32.1 10.837 ;
     RECT  2.712 9.731 3.84 10.307 ;
     RECT  21.612 9.731 22.608 12.851 ;
     RECT  27.336 9.827 28.704 13.139 ;
     RECT  2.712 10.307 4.176 11.459 ;
     RECT  6.12 10.307 7.344 14.341 ;
     RECT  18.912 10.307 20.208 10.355 ;
     RECT  30.936 10.837 32.1 11.029 ;
     RECT  11.16 10.931 12.432 11.459 ;
     RECT  8.112 12.035 9.36 12.611 ;
     RECT  24.312 12.035 25.44 13.139 ;
     RECT  9.384 12.563 10.5 12.611 ;
     RECT  12.432 12.563 13.2 13.573 ;
     RECT  14.712 12.563 15.9 13.715 ;
     RECT  25.464 12.563 26.7 13.139 ;
     RECT  8.112 12.611 8.232 13.669 ;
     RECT  21.612 12.851 22.896 14.677 ;
     RECT  24.312 13.139 24.456 14.101 ;
     RECT  27.336 13.139 28.752 13.763 ;
     RECT  17.16 13.235 18.6 13.715 ;
     RECT  10.812 13.573 12.192 16.789 ;
     RECT  12.216 13.573 13.2 16.645 ;
     RECT  24.408 14.101 24.456 14.437 ;
     RECT  28.752 14.291 28.8 15.541 ;
     RECT  6.744 14.387 7.8 15.251 ;
     RECT  21.768 14.677 22.896 15.491 ;
     RECT  24.456 14.773 25.728 16.019 ;
     RECT  6.12 15.251 7.8 15.925 ;
     RECT  21.72 15.491 22.896 16.643 ;
     RECT  27.384 15.541 28.8 16.117 ;
     RECT  18.912 15.829 19.968 18.275 ;
     RECT  19.992 15.829 21.12 16.595 ;
     RECT  6.12 15.925 7.248 17.461 ;
     RECT  24.456 16.019 26.7 16.981 ;
     RECT  27.384 16.117 28.464 16.595 ;
     RECT  13.656 16.501 14.832 16.931 ;
     RECT  14.856 16.501 15.9 16.931 ;
     RECT  16.212 16.501 17.424 16.643 ;
     RECT  17.448 16.501 18.6 16.643 ;
     RECT  19.992 16.595 21.3 17.557 ;
     RECT  27.144 16.595 28.464 16.981 ;
     RECT  16.212 16.643 18.6 18.133 ;
     RECT  21.612 16.643 22.896 17.989 ;
     RECT  10.812 16.789 12.048 18.709 ;
     RECT  25.176 16.981 26.7 17.461 ;
     RECT  27.144 16.981 28.416 17.315 ;
     RECT  2.712 17.125 3.984 17.555 ;
     RECT  27.144 17.315 28.8 17.605 ;
     RECT  25.368 17.461 26.7 17.989 ;
     RECT  2.712 17.555 4.176 17.653 ;
     RECT  19.992 17.557 21.168 18.275 ;
     RECT  27.72 17.605 28.8 18.757 ;
     RECT  2.808 17.653 4.176 18.757 ;
     RECT  8.856 17.989 10.32 18.133 ;
     RECT  16.212 18.133 17.568 20.099 ;
     RECT  17.592 18.133 18.6 18.565 ;
     RECT  18.912 18.275 21.168 18.277 ;
     RECT  18.912 18.277 21.12 18.709 ;
     RECT  19.848 18.709 21.12 18.995 ;
     RECT  2.856 18.757 4.176 21.109 ;
     RECT  32.52 18.949 33.648 19.957 ;
     RECT  19.848 18.995 21.168 20.485 ;
     RECT  28.152 19.811 29.4 21.109 ;
     RECT  16.212 20.099 18.336 21.109 ;
     RECT  30.696 20.579 31.728 21.155 ;
     RECT  14.472 21.109 15.9 21.157 ;
     RECT  30.696 21.155 31.824 21.203 ;
     RECT  14.568 21.157 15.9 21.541 ;
     RECT  30.696 21.203 31.92 23.555 ;
     RECT  14.568 21.541 15.792 21.637 ;
     RECT  30.696 23.555 31.968 23.628 ;
     RECT  30.744 23.628 31.968 23.651 ;
  END
END hbfd_rly_304_NS
END LIBRARY
